VERSION 5.8 ;
BUSBITCHARS "[]" ;
DIVIDERCHAR "/" ;
UNITS
    DATABASE MICRONS 1000 ;
END UNITS

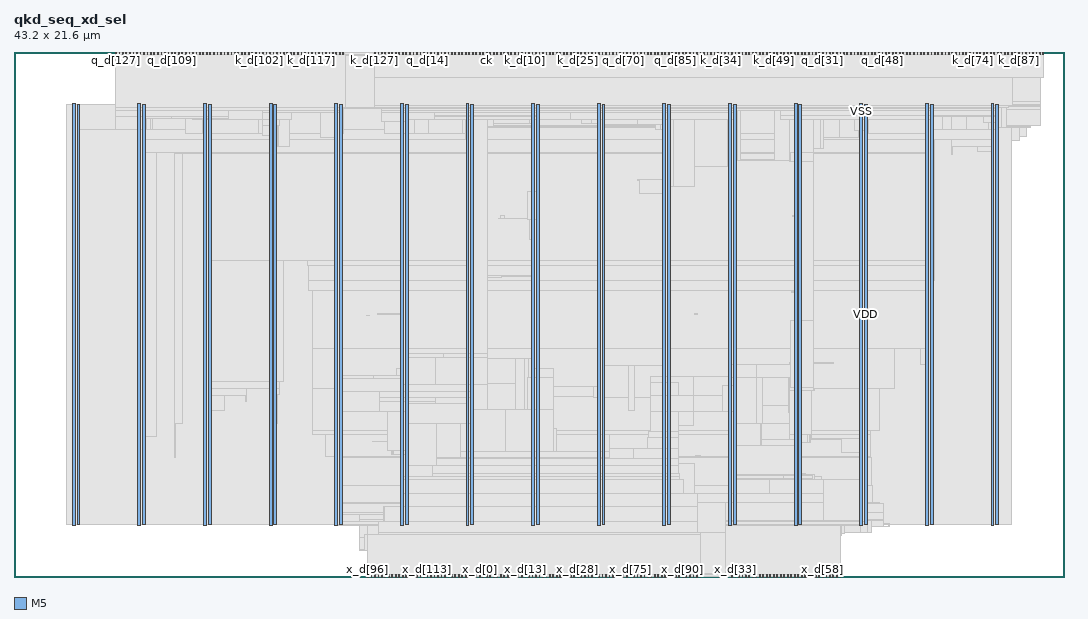
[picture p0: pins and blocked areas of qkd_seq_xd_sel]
MACRO qkd_seq_xd_sel
  FOREIGN qkd_seq_xd_sel 0 0 ;
  CLASS BLOCK ;
  SIZE 43.2 BY 21.6 ;
  PIN ck
    DIRECTION INPUT ;
    USE SIGNAL ;
    PORT
      LAYER M5 ;
        RECT  19.44 21.516 19.464 21.6 ;
    END
  END ck
  PIN k_d[0]
    DIRECTION INPUT ;
    USE SIGNAL ;
    PORT
      LAYER M5 ;
        RECT  19.584 21.516 19.608 21.6 ;
    END
  END k_d[0]
  PIN k_d[100]
    DIRECTION INPUT ;
    USE SIGNAL ;
    PORT
      LAYER M5 ;
        RECT  9.792 21.516 9.816 21.6 ;
    END
  END k_d[100]
  PIN k_d[101]
    DIRECTION INPUT ;
    USE SIGNAL ;
    PORT
      LAYER M5 ;
        RECT  9.936 21.516 9.96 21.6 ;
    END
  END k_d[101]
  PIN k_d[102]
    DIRECTION INPUT ;
    USE SIGNAL ;
    PORT
      LAYER M5 ;
        RECT  10.08 21.516 10.104 21.6 ;
    END
  END k_d[102]
  PIN k_d[103]
    DIRECTION INPUT ;
    USE SIGNAL ;
    PORT
      LAYER M5 ;
        RECT  10.224 21.516 10.248 21.6 ;
    END
  END k_d[103]
  PIN k_d[104]
    DIRECTION INPUT ;
    USE SIGNAL ;
    PORT
      LAYER M5 ;
        RECT  10.368 21.516 10.392 21.6 ;
    END
  END k_d[104]
  PIN k_d[105]
    DIRECTION INPUT ;
    USE SIGNAL ;
    PORT
      LAYER M5 ;
        RECT  10.512 21.516 10.536 21.6 ;
    END
  END k_d[105]
  PIN k_d[106]
    DIRECTION INPUT ;
    USE SIGNAL ;
    PORT
      LAYER M5 ;
        RECT  10.656 21.516 10.68 21.6 ;
    END
  END k_d[106]
  PIN k_d[107]
    DIRECTION INPUT ;
    USE SIGNAL ;
    PORT
      LAYER M5 ;
        RECT  10.8 21.516 10.824 21.6 ;
    END
  END k_d[107]
  PIN k_d[108]
    DIRECTION INPUT ;
    USE SIGNAL ;
    PORT
      LAYER M5 ;
        RECT  10.944 21.516 10.968 21.6 ;
    END
  END k_d[108]
  PIN k_d[109]
    DIRECTION INPUT ;
    USE SIGNAL ;
    PORT
      LAYER M5 ;
        RECT  11.088 21.516 11.112 21.6 ;
    END
  END k_d[109]
  PIN k_d[10]
    DIRECTION INPUT ;
    USE SIGNAL ;
    PORT
      LAYER M5 ;
        RECT  21.024 21.516 21.048 21.6 ;
    END
  END k_d[10]
  PIN k_d[110]
    DIRECTION INPUT ;
    USE SIGNAL ;
    PORT
      LAYER M5 ;
        RECT  11.232 21.516 11.256 21.6 ;
    END
  END k_d[110]
  PIN k_d[111]
    DIRECTION INPUT ;
    USE SIGNAL ;
    PORT
      LAYER M5 ;
        RECT  11.376 21.516 11.4 21.6 ;
    END
  END k_d[111]
  PIN k_d[112]
    DIRECTION INPUT ;
    USE SIGNAL ;
    PORT
      LAYER M5 ;
        RECT  11.52 21.516 11.544 21.6 ;
    END
  END k_d[112]
  PIN k_d[113]
    DIRECTION INPUT ;
    USE SIGNAL ;
    PORT
      LAYER M5 ;
        RECT  11.664 21.516 11.688 21.6 ;
    END
  END k_d[113]
  PIN k_d[114]
    DIRECTION INPUT ;
    USE SIGNAL ;
    PORT
      LAYER M5 ;
        RECT  11.808 21.516 11.832 21.6 ;
    END
  END k_d[114]
  PIN k_d[115]
    DIRECTION INPUT ;
    USE SIGNAL ;
    PORT
      LAYER M5 ;
        RECT  11.952 21.516 11.976 21.6 ;
    END
  END k_d[115]
  PIN k_d[116]
    DIRECTION INPUT ;
    USE SIGNAL ;
    PORT
      LAYER M5 ;
        RECT  12.096 21.516 12.12 21.6 ;
    END
  END k_d[116]
  PIN k_d[117]
    DIRECTION INPUT ;
    USE SIGNAL ;
    PORT
      LAYER M5 ;
        RECT  12.24 21.516 12.264 21.6 ;
    END
  END k_d[117]
  PIN k_d[118]
    DIRECTION INPUT ;
    USE SIGNAL ;
    PORT
      LAYER M5 ;
        RECT  12.384 21.516 12.408 21.6 ;
    END
  END k_d[118]
  PIN k_d[119]
    DIRECTION INPUT ;
    USE SIGNAL ;
    PORT
      LAYER M5 ;
        RECT  12.528 21.516 12.552 21.6 ;
    END
  END k_d[119]
  PIN k_d[11]
    DIRECTION INPUT ;
    USE SIGNAL ;
    PORT
      LAYER M5 ;
        RECT  21.168 21.516 21.192 21.6 ;
    END
  END k_d[11]
  PIN k_d[120]
    DIRECTION INPUT ;
    USE SIGNAL ;
    PORT
      LAYER M5 ;
        RECT  12.672 21.516 12.696 21.6 ;
    END
  END k_d[120]
  PIN k_d[121]
    DIRECTION INPUT ;
    USE SIGNAL ;
    PORT
      LAYER M5 ;
        RECT  12.816 21.516 12.84 21.6 ;
    END
  END k_d[121]
  PIN k_d[122]
    DIRECTION INPUT ;
    USE SIGNAL ;
    PORT
      LAYER M5 ;
        RECT  12.96 21.516 12.984 21.6 ;
    END
  END k_d[122]
  PIN k_d[123]
    DIRECTION INPUT ;
    USE SIGNAL ;
    PORT
      LAYER M5 ;
        RECT  13.104 21.516 13.128 21.6 ;
    END
  END k_d[123]
  PIN k_d[124]
    DIRECTION INPUT ;
    USE SIGNAL ;
    PORT
      LAYER M5 ;
        RECT  13.248 21.516 13.272 21.6 ;
    END
  END k_d[124]
  PIN k_d[125]
    DIRECTION INPUT ;
    USE SIGNAL ;
    PORT
      LAYER M5 ;
        RECT  13.392 21.516 13.416 21.6 ;
    END
  END k_d[125]
  PIN k_d[126]
    DIRECTION INPUT ;
    USE SIGNAL ;
    PORT
      LAYER M5 ;
        RECT  13.536 21.516 13.56 21.6 ;
    END
  END k_d[126]
  PIN k_d[127]
    DIRECTION INPUT ;
    USE SIGNAL ;
    PORT
      LAYER M5 ;
        RECT  14.832 21.516 14.856 21.6 ;
    END
  END k_d[127]
  PIN k_d[12]
    DIRECTION INPUT ;
    USE SIGNAL ;
    PORT
      LAYER M5 ;
        RECT  21.312 21.516 21.336 21.6 ;
    END
  END k_d[12]
  PIN k_d[13]
    DIRECTION INPUT ;
    USE SIGNAL ;
    PORT
      LAYER M5 ;
        RECT  21.456 21.516 21.48 21.6 ;
    END
  END k_d[13]
  PIN k_d[14]
    DIRECTION INPUT ;
    USE SIGNAL ;
    PORT
      LAYER M5 ;
        RECT  21.6 21.516 21.624 21.6 ;
    END
  END k_d[14]
  PIN k_d[15]
    DIRECTION INPUT ;
    USE SIGNAL ;
    PORT
      LAYER M5 ;
        RECT  21.744 21.516 21.768 21.6 ;
    END
  END k_d[15]
  PIN k_d[16]
    DIRECTION INPUT ;
    USE SIGNAL ;
    PORT
      LAYER M5 ;
        RECT  21.888 21.516 21.912 21.6 ;
    END
  END k_d[16]
  PIN k_d[17]
    DIRECTION INPUT ;
    USE SIGNAL ;
    PORT
      LAYER M5 ;
        RECT  22.032 21.516 22.056 21.6 ;
    END
  END k_d[17]
  PIN k_d[18]
    DIRECTION INPUT ;
    USE SIGNAL ;
    PORT
      LAYER M5 ;
        RECT  22.176 21.516 22.2 21.6 ;
    END
  END k_d[18]
  PIN k_d[19]
    DIRECTION INPUT ;
    USE SIGNAL ;
    PORT
      LAYER M5 ;
        RECT  22.32 21.516 22.344 21.6 ;
    END
  END k_d[19]
  PIN k_d[1]
    DIRECTION INPUT ;
    USE SIGNAL ;
    PORT
      LAYER M5 ;
        RECT  19.728 21.516 19.752 21.6 ;
    END
  END k_d[1]
  PIN k_d[20]
    DIRECTION INPUT ;
    USE SIGNAL ;
    PORT
      LAYER M5 ;
        RECT  22.464 21.516 22.488 21.6 ;
    END
  END k_d[20]
  PIN k_d[21]
    DIRECTION INPUT ;
    USE SIGNAL ;
    PORT
      LAYER M5 ;
        RECT  22.608 21.516 22.632 21.6 ;
    END
  END k_d[21]
  PIN k_d[22]
    DIRECTION INPUT ;
    USE SIGNAL ;
    PORT
      LAYER M5 ;
        RECT  22.752 21.516 22.776 21.6 ;
    END
  END k_d[22]
  PIN k_d[23]
    DIRECTION INPUT ;
    USE SIGNAL ;
    PORT
      LAYER M5 ;
        RECT  22.896 21.516 22.92 21.6 ;
    END
  END k_d[23]
  PIN k_d[24]
    DIRECTION INPUT ;
    USE SIGNAL ;
    PORT
      LAYER M5 ;
        RECT  23.04 21.516 23.064 21.6 ;
    END
  END k_d[24]
  PIN k_d[25]
    DIRECTION INPUT ;
    USE SIGNAL ;
    PORT
      LAYER M5 ;
        RECT  23.184 21.516 23.208 21.6 ;
    END
  END k_d[25]
  PIN k_d[26]
    DIRECTION INPUT ;
    USE SIGNAL ;
    PORT
      LAYER M5 ;
        RECT  23.328 21.516 23.352 21.6 ;
    END
  END k_d[26]
  PIN k_d[27]
    DIRECTION INPUT ;
    USE SIGNAL ;
    PORT
      LAYER M5 ;
        RECT  23.472 21.516 23.496 21.6 ;
    END
  END k_d[27]
  PIN k_d[28]
    DIRECTION INPUT ;
    USE SIGNAL ;
    PORT
      LAYER M5 ;
        RECT  23.616 21.516 23.64 21.6 ;
    END
  END k_d[28]
  PIN k_d[29]
    DIRECTION INPUT ;
    USE SIGNAL ;
    PORT
      LAYER M5 ;
        RECT  23.76 21.516 23.784 21.6 ;
    END
  END k_d[29]
  PIN k_d[2]
    DIRECTION INPUT ;
    USE SIGNAL ;
    PORT
      LAYER M5 ;
        RECT  19.872 21.516 19.896 21.6 ;
    END
  END k_d[2]
  PIN k_d[30]
    DIRECTION INPUT ;
    USE SIGNAL ;
    PORT
      LAYER M5 ;
        RECT  23.904 21.516 23.928 21.6 ;
    END
  END k_d[30]
  PIN k_d[31]
    DIRECTION INPUT ;
    USE SIGNAL ;
    PORT
      LAYER M5 ;
        RECT  28.656 21.516 28.68 21.6 ;
    END
  END k_d[31]
  PIN k_d[32]
    DIRECTION INPUT ;
    USE SIGNAL ;
    PORT
      LAYER M5 ;
        RECT  28.8 21.516 28.824 21.6 ;
    END
  END k_d[32]
  PIN k_d[33]
    DIRECTION INPUT ;
    USE SIGNAL ;
    PORT
      LAYER M5 ;
        RECT  28.944 21.516 28.968 21.6 ;
    END
  END k_d[33]
  PIN k_d[34]
    DIRECTION INPUT ;
    USE SIGNAL ;
    PORT
      LAYER M5 ;
        RECT  29.088 21.516 29.112 21.6 ;
    END
  END k_d[34]
  PIN k_d[35]
    DIRECTION INPUT ;
    USE SIGNAL ;
    PORT
      LAYER M5 ;
        RECT  29.232 21.516 29.256 21.6 ;
    END
  END k_d[35]
  PIN k_d[36]
    DIRECTION INPUT ;
    USE SIGNAL ;
    PORT
      LAYER M5 ;
        RECT  29.376 21.516 29.4 21.6 ;
    END
  END k_d[36]
  PIN k_d[37]
    DIRECTION INPUT ;
    USE SIGNAL ;
    PORT
      LAYER M5 ;
        RECT  29.52 21.516 29.544 21.6 ;
    END
  END k_d[37]
  PIN k_d[38]
    DIRECTION INPUT ;
    USE SIGNAL ;
    PORT
      LAYER M5 ;
        RECT  29.664 21.516 29.688 21.6 ;
    END
  END k_d[38]
  PIN k_d[39]
    DIRECTION INPUT ;
    USE SIGNAL ;
    PORT
      LAYER M5 ;
        RECT  29.808 21.516 29.832 21.6 ;
    END
  END k_d[39]
  PIN k_d[3]
    DIRECTION INPUT ;
    USE SIGNAL ;
    PORT
      LAYER M5 ;
        RECT  20.016 21.516 20.04 21.6 ;
    END
  END k_d[3]
  PIN k_d[40]
    DIRECTION INPUT ;
    USE SIGNAL ;
    PORT
      LAYER M5 ;
        RECT  29.952 21.516 29.976 21.6 ;
    END
  END k_d[40]
  PIN k_d[41]
    DIRECTION INPUT ;
    USE SIGNAL ;
    PORT
      LAYER M5 ;
        RECT  30.096 21.516 30.12 21.6 ;
    END
  END k_d[41]
  PIN k_d[42]
    DIRECTION INPUT ;
    USE SIGNAL ;
    PORT
      LAYER M5 ;
        RECT  30.24 21.516 30.264 21.6 ;
    END
  END k_d[42]
  PIN k_d[43]
    DIRECTION INPUT ;
    USE SIGNAL ;
    PORT
      LAYER M5 ;
        RECT  30.384 21.516 30.408 21.6 ;
    END
  END k_d[43]
  PIN k_d[44]
    DIRECTION INPUT ;
    USE SIGNAL ;
    PORT
      LAYER M5 ;
        RECT  30.528 21.516 30.552 21.6 ;
    END
  END k_d[44]
  PIN k_d[45]
    DIRECTION INPUT ;
    USE SIGNAL ;
    PORT
      LAYER M5 ;
        RECT  30.672 21.516 30.696 21.6 ;
    END
  END k_d[45]
  PIN k_d[46]
    DIRECTION INPUT ;
    USE SIGNAL ;
    PORT
      LAYER M5 ;
        RECT  30.816 21.516 30.84 21.6 ;
    END
  END k_d[46]
  PIN k_d[47]
    DIRECTION INPUT ;
    USE SIGNAL ;
    PORT
      LAYER M5 ;
        RECT  30.96 21.516 30.984 21.6 ;
    END
  END k_d[47]
  PIN k_d[48]
    DIRECTION INPUT ;
    USE SIGNAL ;
    PORT
      LAYER M5 ;
        RECT  31.104 21.516 31.128 21.6 ;
    END
  END k_d[48]
  PIN k_d[49]
    DIRECTION INPUT ;
    USE SIGNAL ;
    PORT
      LAYER M5 ;
        RECT  31.248 21.516 31.272 21.6 ;
    END
  END k_d[49]
  PIN k_d[4]
    DIRECTION INPUT ;
    USE SIGNAL ;
    PORT
      LAYER M5 ;
        RECT  20.16 21.516 20.184 21.6 ;
    END
  END k_d[4]
  PIN k_d[50]
    DIRECTION INPUT ;
    USE SIGNAL ;
    PORT
      LAYER M5 ;
        RECT  31.392 21.516 31.416 21.6 ;
    END
  END k_d[50]
  PIN k_d[51]
    DIRECTION INPUT ;
    USE SIGNAL ;
    PORT
      LAYER M5 ;
        RECT  31.536 21.516 31.56 21.6 ;
    END
  END k_d[51]
  PIN k_d[52]
    DIRECTION INPUT ;
    USE SIGNAL ;
    PORT
      LAYER M5 ;
        RECT  31.68 21.516 31.704 21.6 ;
    END
  END k_d[52]
  PIN k_d[53]
    DIRECTION INPUT ;
    USE SIGNAL ;
    PORT
      LAYER M5 ;
        RECT  31.824 21.516 31.848 21.6 ;
    END
  END k_d[53]
  PIN k_d[54]
    DIRECTION INPUT ;
    USE SIGNAL ;
    PORT
      LAYER M5 ;
        RECT  31.968 21.516 31.992 21.6 ;
    END
  END k_d[54]
  PIN k_d[55]
    DIRECTION INPUT ;
    USE SIGNAL ;
    PORT
      LAYER M5 ;
        RECT  32.112 21.516 32.136 21.6 ;
    END
  END k_d[55]
  PIN k_d[56]
    DIRECTION INPUT ;
    USE SIGNAL ;
    PORT
      LAYER M5 ;
        RECT  32.256 21.516 32.28 21.6 ;
    END
  END k_d[56]
  PIN k_d[57]
    DIRECTION INPUT ;
    USE SIGNAL ;
    PORT
      LAYER M5 ;
        RECT  32.4 21.516 32.424 21.6 ;
    END
  END k_d[57]
  PIN k_d[58]
    DIRECTION INPUT ;
    USE SIGNAL ;
    PORT
      LAYER M5 ;
        RECT  32.544 21.516 32.568 21.6 ;
    END
  END k_d[58]
  PIN k_d[59]
    DIRECTION INPUT ;
    USE SIGNAL ;
    PORT
      LAYER M5 ;
        RECT  32.688 21.516 32.712 21.6 ;
    END
  END k_d[59]
  PIN k_d[5]
    DIRECTION INPUT ;
    USE SIGNAL ;
    PORT
      LAYER M5 ;
        RECT  20.304 21.516 20.328 21.6 ;
    END
  END k_d[5]
  PIN k_d[60]
    DIRECTION INPUT ;
    USE SIGNAL ;
    PORT
      LAYER M5 ;
        RECT  32.832 21.516 32.856 21.6 ;
    END
  END k_d[60]
  PIN k_d[61]
    DIRECTION INPUT ;
    USE SIGNAL ;
    PORT
      LAYER M5 ;
        RECT  32.976 21.516 33 21.6 ;
    END
  END k_d[61]
  PIN k_d[62]
    DIRECTION INPUT ;
    USE SIGNAL ;
    PORT
      LAYER M5 ;
        RECT  33.12 21.516 33.144 21.6 ;
    END
  END k_d[62]
  PIN k_d[63]
    DIRECTION INPUT ;
    USE SIGNAL ;
    PORT
      LAYER M5 ;
        RECT  37.872 21.516 37.896 21.6 ;
    END
  END k_d[63]
  PIN k_d[64]
    DIRECTION INPUT ;
    USE SIGNAL ;
    PORT
      LAYER M5 ;
        RECT  38.016 21.516 38.04 21.6 ;
    END
  END k_d[64]
  PIN k_d[65]
    DIRECTION INPUT ;
    USE SIGNAL ;
    PORT
      LAYER M5 ;
        RECT  38.16 21.516 38.184 21.6 ;
    END
  END k_d[65]
  PIN k_d[66]
    DIRECTION INPUT ;
    USE SIGNAL ;
    PORT
      LAYER M5 ;
        RECT  38.304 21.516 38.328 21.6 ;
    END
  END k_d[66]
  PIN k_d[67]
    DIRECTION INPUT ;
    USE SIGNAL ;
    PORT
      LAYER M5 ;
        RECT  38.448 21.516 38.472 21.6 ;
    END
  END k_d[67]
  PIN k_d[68]
    DIRECTION INPUT ;
    USE SIGNAL ;
    PORT
      LAYER M5 ;
        RECT  38.592 21.516 38.616 21.6 ;
    END
  END k_d[68]
  PIN k_d[69]
    DIRECTION INPUT ;
    USE SIGNAL ;
    PORT
      LAYER M5 ;
        RECT  38.736 21.516 38.76 21.6 ;
    END
  END k_d[69]
  PIN k_d[6]
    DIRECTION INPUT ;
    USE SIGNAL ;
    PORT
      LAYER M5 ;
        RECT  20.448 21.516 20.472 21.6 ;
    END
  END k_d[6]
  PIN k_d[70]
    DIRECTION INPUT ;
    USE SIGNAL ;
    PORT
      LAYER M5 ;
        RECT  38.88 21.516 38.904 21.6 ;
    END
  END k_d[70]
  PIN k_d[71]
    DIRECTION INPUT ;
    USE SIGNAL ;
    PORT
      LAYER M5 ;
        RECT  39.024 21.516 39.048 21.6 ;
    END
  END k_d[71]
  PIN k_d[72]
    DIRECTION INPUT ;
    USE SIGNAL ;
    PORT
      LAYER M5 ;
        RECT  39.168 21.516 39.192 21.6 ;
    END
  END k_d[72]
  PIN k_d[73]
    DIRECTION INPUT ;
    USE SIGNAL ;
    PORT
      LAYER M5 ;
        RECT  39.312 21.516 39.336 21.6 ;
    END
  END k_d[73]
  PIN k_d[74]
    DIRECTION INPUT ;
    USE SIGNAL ;
    PORT
      LAYER M5 ;
        RECT  39.456 21.516 39.48 21.6 ;
    END
  END k_d[74]
  PIN k_d[75]
    DIRECTION INPUT ;
    USE SIGNAL ;
    PORT
      LAYER M5 ;
        RECT  39.6 21.516 39.624 21.6 ;
    END
  END k_d[75]
  PIN k_d[76]
    DIRECTION INPUT ;
    USE SIGNAL ;
    PORT
      LAYER M5 ;
        RECT  39.744 21.516 39.768 21.6 ;
    END
  END k_d[76]
  PIN k_d[77]
    DIRECTION INPUT ;
    USE SIGNAL ;
    PORT
      LAYER M5 ;
        RECT  39.888 21.516 39.912 21.6 ;
    END
  END k_d[77]
  PIN k_d[78]
    DIRECTION INPUT ;
    USE SIGNAL ;
    PORT
      LAYER M5 ;
        RECT  40.032 21.516 40.056 21.6 ;
    END
  END k_d[78]
  PIN k_d[79]
    DIRECTION INPUT ;
    USE SIGNAL ;
    PORT
      LAYER M5 ;
        RECT  40.176 21.516 40.2 21.6 ;
    END
  END k_d[79]
  PIN k_d[7]
    DIRECTION INPUT ;
    USE SIGNAL ;
    PORT
      LAYER M5 ;
        RECT  20.592 21.516 20.616 21.6 ;
    END
  END k_d[7]
  PIN k_d[80]
    DIRECTION INPUT ;
    USE SIGNAL ;
    PORT
      LAYER M5 ;
        RECT  40.32 21.516 40.344 21.6 ;
    END
  END k_d[80]
  PIN k_d[81]
    DIRECTION INPUT ;
    USE SIGNAL ;
    PORT
      LAYER M5 ;
        RECT  40.464 21.516 40.488 21.6 ;
    END
  END k_d[81]
  PIN k_d[82]
    DIRECTION INPUT ;
    USE SIGNAL ;
    PORT
      LAYER M5 ;
        RECT  40.608 21.516 40.632 21.6 ;
    END
  END k_d[82]
  PIN k_d[83]
    DIRECTION INPUT ;
    USE SIGNAL ;
    PORT
      LAYER M5 ;
        RECT  40.752 21.516 40.776 21.6 ;
    END
  END k_d[83]
  PIN k_d[84]
    DIRECTION INPUT ;
    USE SIGNAL ;
    PORT
      LAYER M5 ;
        RECT  40.896 21.516 40.92 21.6 ;
    END
  END k_d[84]
  PIN k_d[85]
    DIRECTION INPUT ;
    USE SIGNAL ;
    PORT
      LAYER M5 ;
        RECT  41.04 21.516 41.064 21.6 ;
    END
  END k_d[85]
  PIN k_d[86]
    DIRECTION INPUT ;
    USE SIGNAL ;
    PORT
      LAYER M5 ;
        RECT  41.184 21.516 41.208 21.6 ;
    END
  END k_d[86]
  PIN k_d[87]
    DIRECTION INPUT ;
    USE SIGNAL ;
    PORT
      LAYER M5 ;
        RECT  41.328 21.516 41.352 21.6 ;
    END
  END k_d[87]
  PIN k_d[88]
    DIRECTION INPUT ;
    USE SIGNAL ;
    PORT
      LAYER M5 ;
        RECT  41.472 21.516 41.496 21.6 ;
    END
  END k_d[88]
  PIN k_d[89]
    DIRECTION INPUT ;
    USE SIGNAL ;
    PORT
      LAYER M5 ;
        RECT  41.616 21.516 41.64 21.6 ;
    END
  END k_d[89]
  PIN k_d[8]
    DIRECTION INPUT ;
    USE SIGNAL ;
    PORT
      LAYER M5 ;
        RECT  20.736 21.516 20.76 21.6 ;
    END
  END k_d[8]
  PIN k_d[90]
    DIRECTION INPUT ;
    USE SIGNAL ;
    PORT
      LAYER M5 ;
        RECT  41.76 21.516 41.784 21.6 ;
    END
  END k_d[90]
  PIN k_d[91]
    DIRECTION INPUT ;
    USE SIGNAL ;
    PORT
      LAYER M5 ;
        RECT  41.904 21.516 41.928 21.6 ;
    END
  END k_d[91]
  PIN k_d[92]
    DIRECTION INPUT ;
    USE SIGNAL ;
    PORT
      LAYER M5 ;
        RECT  42.048 21.516 42.072 21.6 ;
    END
  END k_d[92]
  PIN k_d[93]
    DIRECTION INPUT ;
    USE SIGNAL ;
    PORT
      LAYER M5 ;
        RECT  42.192 21.516 42.216 21.6 ;
    END
  END k_d[93]
  PIN k_d[94]
    DIRECTION INPUT ;
    USE SIGNAL ;
    PORT
      LAYER M5 ;
        RECT  42.336 21.516 42.36 21.6 ;
    END
  END k_d[94]
  PIN k_d[95]
    DIRECTION INPUT ;
    USE SIGNAL ;
    PORT
      LAYER M5 ;
        RECT  9.072 21.516 9.096 21.6 ;
    END
  END k_d[95]
  PIN k_d[96]
    DIRECTION INPUT ;
    USE SIGNAL ;
    PORT
      LAYER M5 ;
        RECT  9.216 21.516 9.24 21.6 ;
    END
  END k_d[96]
  PIN k_d[97]
    DIRECTION INPUT ;
    USE SIGNAL ;
    PORT
      LAYER M5 ;
        RECT  9.36 21.516 9.384 21.6 ;
    END
  END k_d[97]
  PIN k_d[98]
    DIRECTION INPUT ;
    USE SIGNAL ;
    PORT
      LAYER M5 ;
        RECT  9.504 21.516 9.528 21.6 ;
    END
  END k_d[98]
  PIN k_d[99]
    DIRECTION INPUT ;
    USE SIGNAL ;
    PORT
      LAYER M5 ;
        RECT  9.648 21.516 9.672 21.6 ;
    END
  END k_d[99]
  PIN k_d[9]
    DIRECTION INPUT ;
    USE SIGNAL ;
    PORT
      LAYER M5 ;
        RECT  20.88 21.516 20.904 21.6 ;
    END
  END k_d[9]
  PIN q_d[0]
    DIRECTION INPUT ;
    USE SIGNAL ;
    PORT
      LAYER M5 ;
        RECT  14.976 21.516 15 21.6 ;
    END
  END q_d[0]
  PIN q_d[100]
    DIRECTION INPUT ;
    USE SIGNAL ;
    PORT
      LAYER M5 ;
        RECT  5.184 21.516 5.208 21.6 ;
    END
  END q_d[100]
  PIN q_d[101]
    DIRECTION INPUT ;
    USE SIGNAL ;
    PORT
      LAYER M5 ;
        RECT  5.328 21.516 5.352 21.6 ;
    END
  END q_d[101]
  PIN q_d[102]
    DIRECTION INPUT ;
    USE SIGNAL ;
    PORT
      LAYER M5 ;
        RECT  5.472 21.516 5.496 21.6 ;
    END
  END q_d[102]
  PIN q_d[103]
    DIRECTION INPUT ;
    USE SIGNAL ;
    PORT
      LAYER M5 ;
        RECT  5.616 21.516 5.64 21.6 ;
    END
  END q_d[103]
  PIN q_d[104]
    DIRECTION INPUT ;
    USE SIGNAL ;
    PORT
      LAYER M5 ;
        RECT  5.76 21.516 5.784 21.6 ;
    END
  END q_d[104]
  PIN q_d[105]
    DIRECTION INPUT ;
    USE SIGNAL ;
    PORT
      LAYER M5 ;
        RECT  5.904 21.516 5.928 21.6 ;
    END
  END q_d[105]
  PIN q_d[106]
    DIRECTION INPUT ;
    USE SIGNAL ;
    PORT
      LAYER M5 ;
        RECT  6.048 21.516 6.072 21.6 ;
    END
  END q_d[106]
  PIN q_d[107]
    DIRECTION INPUT ;
    USE SIGNAL ;
    PORT
      LAYER M5 ;
        RECT  6.192 21.516 6.216 21.6 ;
    END
  END q_d[107]
  PIN q_d[108]
    DIRECTION INPUT ;
    USE SIGNAL ;
    PORT
      LAYER M5 ;
        RECT  6.336 21.516 6.36 21.6 ;
    END
  END q_d[108]
  PIN q_d[109]
    DIRECTION INPUT ;
    USE SIGNAL ;
    PORT
      LAYER M5 ;
        RECT  6.48 21.516 6.504 21.6 ;
    END
  END q_d[109]
  PIN q_d[10]
    DIRECTION INPUT ;
    USE SIGNAL ;
    PORT
      LAYER M5 ;
        RECT  16.416 21.516 16.44 21.6 ;
    END
  END q_d[10]
  PIN q_d[110]
    DIRECTION INPUT ;
    USE SIGNAL ;
    PORT
      LAYER M5 ;
        RECT  6.624 21.516 6.648 21.6 ;
    END
  END q_d[110]
  PIN q_d[111]
    DIRECTION INPUT ;
    USE SIGNAL ;
    PORT
      LAYER M5 ;
        RECT  6.768 21.516 6.792 21.6 ;
    END
  END q_d[111]
  PIN q_d[112]
    DIRECTION INPUT ;
    USE SIGNAL ;
    PORT
      LAYER M5 ;
        RECT  6.912 21.516 6.936 21.6 ;
    END
  END q_d[112]
  PIN q_d[113]
    DIRECTION INPUT ;
    USE SIGNAL ;
    PORT
      LAYER M5 ;
        RECT  7.056 21.516 7.08 21.6 ;
    END
  END q_d[113]
  PIN q_d[114]
    DIRECTION INPUT ;
    USE SIGNAL ;
    PORT
      LAYER M5 ;
        RECT  7.2 21.516 7.224 21.6 ;
    END
  END q_d[114]
  PIN q_d[115]
    DIRECTION INPUT ;
    USE SIGNAL ;
    PORT
      LAYER M5 ;
        RECT  7.344 21.516 7.368 21.6 ;
    END
  END q_d[115]
  PIN q_d[116]
    DIRECTION INPUT ;
    USE SIGNAL ;
    PORT
      LAYER M5 ;
        RECT  7.488 21.516 7.512 21.6 ;
    END
  END q_d[116]
  PIN q_d[117]
    DIRECTION INPUT ;
    USE SIGNAL ;
    PORT
      LAYER M5 ;
        RECT  7.632 21.516 7.656 21.6 ;
    END
  END q_d[117]
  PIN q_d[118]
    DIRECTION INPUT ;
    USE SIGNAL ;
    PORT
      LAYER M5 ;
        RECT  7.776 21.516 7.8 21.6 ;
    END
  END q_d[118]
  PIN q_d[119]
    DIRECTION INPUT ;
    USE SIGNAL ;
    PORT
      LAYER M5 ;
        RECT  7.92 21.516 7.944 21.6 ;
    END
  END q_d[119]
  PIN q_d[11]
    DIRECTION INPUT ;
    USE SIGNAL ;
    PORT
      LAYER M5 ;
        RECT  16.56 21.516 16.584 21.6 ;
    END
  END q_d[11]
  PIN q_d[120]
    DIRECTION INPUT ;
    USE SIGNAL ;
    PORT
      LAYER M5 ;
        RECT  8.064 21.516 8.088 21.6 ;
    END
  END q_d[120]
  PIN q_d[121]
    DIRECTION INPUT ;
    USE SIGNAL ;
    PORT
      LAYER M5 ;
        RECT  8.208 21.516 8.232 21.6 ;
    END
  END q_d[121]
  PIN q_d[122]
    DIRECTION INPUT ;
    USE SIGNAL ;
    PORT
      LAYER M5 ;
        RECT  8.352 21.516 8.376 21.6 ;
    END
  END q_d[122]
  PIN q_d[123]
    DIRECTION INPUT ;
    USE SIGNAL ;
    PORT
      LAYER M5 ;
        RECT  8.496 21.516 8.52 21.6 ;
    END
  END q_d[123]
  PIN q_d[124]
    DIRECTION INPUT ;
    USE SIGNAL ;
    PORT
      LAYER M5 ;
        RECT  8.64 21.516 8.664 21.6 ;
    END
  END q_d[124]
  PIN q_d[125]
    DIRECTION INPUT ;
    USE SIGNAL ;
    PORT
      LAYER M5 ;
        RECT  8.784 21.516 8.808 21.6 ;
    END
  END q_d[125]
  PIN q_d[126]
    DIRECTION INPUT ;
    USE SIGNAL ;
    PORT
      LAYER M5 ;
        RECT  8.928 21.516 8.952 21.6 ;
    END
  END q_d[126]
  PIN q_d[127]
    DIRECTION INPUT ;
    USE SIGNAL ;
    PORT
      LAYER M5 ;
        RECT  4.176 21.516 4.2 21.6 ;
    END
  END q_d[127]
  PIN q_d[12]
    DIRECTION INPUT ;
    USE SIGNAL ;
    PORT
      LAYER M5 ;
        RECT  16.704 21.516 16.728 21.6 ;
    END
  END q_d[12]
  PIN q_d[13]
    DIRECTION INPUT ;
    USE SIGNAL ;
    PORT
      LAYER M5 ;
        RECT  16.848 21.516 16.872 21.6 ;
    END
  END q_d[13]
  PIN q_d[14]
    DIRECTION INPUT ;
    USE SIGNAL ;
    PORT
      LAYER M5 ;
        RECT  16.992 21.516 17.016 21.6 ;
    END
  END q_d[14]
  PIN q_d[15]
    DIRECTION INPUT ;
    USE SIGNAL ;
    PORT
      LAYER M5 ;
        RECT  17.136 21.516 17.16 21.6 ;
    END
  END q_d[15]
  PIN q_d[16]
    DIRECTION INPUT ;
    USE SIGNAL ;
    PORT
      LAYER M5 ;
        RECT  17.28 21.516 17.304 21.6 ;
    END
  END q_d[16]
  PIN q_d[17]
    DIRECTION INPUT ;
    USE SIGNAL ;
    PORT
      LAYER M5 ;
        RECT  17.424 21.516 17.448 21.6 ;
    END
  END q_d[17]
  PIN q_d[18]
    DIRECTION INPUT ;
    USE SIGNAL ;
    PORT
      LAYER M5 ;
        RECT  17.568 21.516 17.592 21.6 ;
    END
  END q_d[18]
  PIN q_d[19]
    DIRECTION INPUT ;
    USE SIGNAL ;
    PORT
      LAYER M5 ;
        RECT  17.712 21.516 17.736 21.6 ;
    END
  END q_d[19]
  PIN q_d[1]
    DIRECTION INPUT ;
    USE SIGNAL ;
    PORT
      LAYER M5 ;
        RECT  15.12 21.516 15.144 21.6 ;
    END
  END q_d[1]
  PIN q_d[20]
    DIRECTION INPUT ;
    USE SIGNAL ;
    PORT
      LAYER M5 ;
        RECT  17.856 21.516 17.88 21.6 ;
    END
  END q_d[20]
  PIN q_d[21]
    DIRECTION INPUT ;
    USE SIGNAL ;
    PORT
      LAYER M5 ;
        RECT  18 21.516 18.024 21.6 ;
    END
  END q_d[21]
  PIN q_d[22]
    DIRECTION INPUT ;
    USE SIGNAL ;
    PORT
      LAYER M5 ;
        RECT  18.144 21.516 18.168 21.6 ;
    END
  END q_d[22]
  PIN q_d[23]
    DIRECTION INPUT ;
    USE SIGNAL ;
    PORT
      LAYER M5 ;
        RECT  18.288 21.516 18.312 21.6 ;
    END
  END q_d[23]
  PIN q_d[24]
    DIRECTION INPUT ;
    USE SIGNAL ;
    PORT
      LAYER M5 ;
        RECT  18.432 21.516 18.456 21.6 ;
    END
  END q_d[24]
  PIN q_d[25]
    DIRECTION INPUT ;
    USE SIGNAL ;
    PORT
      LAYER M5 ;
        RECT  18.576 21.516 18.6 21.6 ;
    END
  END q_d[25]
  PIN q_d[26]
    DIRECTION INPUT ;
    USE SIGNAL ;
    PORT
      LAYER M5 ;
        RECT  18.72 21.516 18.744 21.6 ;
    END
  END q_d[26]
  PIN q_d[27]
    DIRECTION INPUT ;
    USE SIGNAL ;
    PORT
      LAYER M5 ;
        RECT  18.864 21.516 18.888 21.6 ;
    END
  END q_d[27]
  PIN q_d[28]
    DIRECTION INPUT ;
    USE SIGNAL ;
    PORT
      LAYER M5 ;
        RECT  19.008 21.516 19.032 21.6 ;
    END
  END q_d[28]
  PIN q_d[29]
    DIRECTION INPUT ;
    USE SIGNAL ;
    PORT
      LAYER M5 ;
        RECT  19.152 21.516 19.176 21.6 ;
    END
  END q_d[29]
  PIN q_d[2]
    DIRECTION INPUT ;
    USE SIGNAL ;
    PORT
      LAYER M5 ;
        RECT  15.264 21.516 15.288 21.6 ;
    END
  END q_d[2]
  PIN q_d[30]
    DIRECTION INPUT ;
    USE SIGNAL ;
    PORT
      LAYER M5 ;
        RECT  19.296 21.516 19.32 21.6 ;
    END
  END q_d[30]
  PIN q_d[31]
    DIRECTION INPUT ;
    USE SIGNAL ;
    PORT
      LAYER M5 ;
        RECT  33.264 21.516 33.288 21.6 ;
    END
  END q_d[31]
  PIN q_d[32]
    DIRECTION INPUT ;
    USE SIGNAL ;
    PORT
      LAYER M5 ;
        RECT  33.408 21.516 33.432 21.6 ;
    END
  END q_d[32]
  PIN q_d[33]
    DIRECTION INPUT ;
    USE SIGNAL ;
    PORT
      LAYER M5 ;
        RECT  33.552 21.516 33.576 21.6 ;
    END
  END q_d[33]
  PIN q_d[34]
    DIRECTION INPUT ;
    USE SIGNAL ;
    PORT
      LAYER M5 ;
        RECT  33.696 21.516 33.72 21.6 ;
    END
  END q_d[34]
  PIN q_d[35]
    DIRECTION INPUT ;
    USE SIGNAL ;
    PORT
      LAYER M5 ;
        RECT  33.84 21.516 33.864 21.6 ;
    END
  END q_d[35]
  PIN q_d[36]
    DIRECTION INPUT ;
    USE SIGNAL ;
    PORT
      LAYER M5 ;
        RECT  33.984 21.516 34.008 21.6 ;
    END
  END q_d[36]
  PIN q_d[37]
    DIRECTION INPUT ;
    USE SIGNAL ;
    PORT
      LAYER M5 ;
        RECT  34.128 21.516 34.152 21.6 ;
    END
  END q_d[37]
  PIN q_d[38]
    DIRECTION INPUT ;
    USE SIGNAL ;
    PORT
      LAYER M5 ;
        RECT  34.272 21.516 34.296 21.6 ;
    END
  END q_d[38]
  PIN q_d[39]
    DIRECTION INPUT ;
    USE SIGNAL ;
    PORT
      LAYER M5 ;
        RECT  34.416 21.516 34.44 21.6 ;
    END
  END q_d[39]
  PIN q_d[3]
    DIRECTION INPUT ;
    USE SIGNAL ;
    PORT
      LAYER M5 ;
        RECT  15.408 21.516 15.432 21.6 ;
    END
  END q_d[3]
  PIN q_d[40]
    DIRECTION INPUT ;
    USE SIGNAL ;
    PORT
      LAYER M5 ;
        RECT  34.56 21.516 34.584 21.6 ;
    END
  END q_d[40]
  PIN q_d[41]
    DIRECTION INPUT ;
    USE SIGNAL ;
    PORT
      LAYER M5 ;
        RECT  34.704 21.516 34.728 21.6 ;
    END
  END q_d[41]
  PIN q_d[42]
    DIRECTION INPUT ;
    USE SIGNAL ;
    PORT
      LAYER M5 ;
        RECT  34.848 21.516 34.872 21.6 ;
    END
  END q_d[42]
  PIN q_d[43]
    DIRECTION INPUT ;
    USE SIGNAL ;
    PORT
      LAYER M5 ;
        RECT  34.992 21.516 35.016 21.6 ;
    END
  END q_d[43]
  PIN q_d[44]
    DIRECTION INPUT ;
    USE SIGNAL ;
    PORT
      LAYER M5 ;
        RECT  35.136 21.516 35.16 21.6 ;
    END
  END q_d[44]
  PIN q_d[45]
    DIRECTION INPUT ;
    USE SIGNAL ;
    PORT
      LAYER M5 ;
        RECT  35.28 21.516 35.304 21.6 ;
    END
  END q_d[45]
  PIN q_d[46]
    DIRECTION INPUT ;
    USE SIGNAL ;
    PORT
      LAYER M5 ;
        RECT  35.424 21.516 35.448 21.6 ;
    END
  END q_d[46]
  PIN q_d[47]
    DIRECTION INPUT ;
    USE SIGNAL ;
    PORT
      LAYER M5 ;
        RECT  35.568 21.516 35.592 21.6 ;
    END
  END q_d[47]
  PIN q_d[48]
    DIRECTION INPUT ;
    USE SIGNAL ;
    PORT
      LAYER M5 ;
        RECT  35.712 21.516 35.736 21.6 ;
    END
  END q_d[48]
  PIN q_d[49]
    DIRECTION INPUT ;
    USE SIGNAL ;
    PORT
      LAYER M5 ;
        RECT  35.856 21.516 35.88 21.6 ;
    END
  END q_d[49]
  PIN q_d[4]
    DIRECTION INPUT ;
    USE SIGNAL ;
    PORT
      LAYER M5 ;
        RECT  15.552 21.516 15.576 21.6 ;
    END
  END q_d[4]
  PIN q_d[50]
    DIRECTION INPUT ;
    USE SIGNAL ;
    PORT
      LAYER M5 ;
        RECT  36 21.516 36.024 21.6 ;
    END
  END q_d[50]
  PIN q_d[51]
    DIRECTION INPUT ;
    USE SIGNAL ;
    PORT
      LAYER M5 ;
        RECT  36.144 21.516 36.168 21.6 ;
    END
  END q_d[51]
  PIN q_d[52]
    DIRECTION INPUT ;
    USE SIGNAL ;
    PORT
      LAYER M5 ;
        RECT  36.288 21.516 36.312 21.6 ;
    END
  END q_d[52]
  PIN q_d[53]
    DIRECTION INPUT ;
    USE SIGNAL ;
    PORT
      LAYER M5 ;
        RECT  36.432 21.516 36.456 21.6 ;
    END
  END q_d[53]
  PIN q_d[54]
    DIRECTION INPUT ;
    USE SIGNAL ;
    PORT
      LAYER M5 ;
        RECT  36.576 21.516 36.6 21.6 ;
    END
  END q_d[54]
  PIN q_d[55]
    DIRECTION INPUT ;
    USE SIGNAL ;
    PORT
      LAYER M5 ;
        RECT  36.72 21.516 36.744 21.6 ;
    END
  END q_d[55]
  PIN q_d[56]
    DIRECTION INPUT ;
    USE SIGNAL ;
    PORT
      LAYER M5 ;
        RECT  36.864 21.516 36.888 21.6 ;
    END
  END q_d[56]
  PIN q_d[57]
    DIRECTION INPUT ;
    USE SIGNAL ;
    PORT
      LAYER M5 ;
        RECT  37.008 21.516 37.032 21.6 ;
    END
  END q_d[57]
  PIN q_d[58]
    DIRECTION INPUT ;
    USE SIGNAL ;
    PORT
      LAYER M5 ;
        RECT  37.152 21.516 37.176 21.6 ;
    END
  END q_d[58]
  PIN q_d[59]
    DIRECTION INPUT ;
    USE SIGNAL ;
    PORT
      LAYER M5 ;
        RECT  37.296 21.516 37.32 21.6 ;
    END
  END q_d[59]
  PIN q_d[5]
    DIRECTION INPUT ;
    USE SIGNAL ;
    PORT
      LAYER M5 ;
        RECT  15.696 21.516 15.72 21.6 ;
    END
  END q_d[5]
  PIN q_d[60]
    DIRECTION INPUT ;
    USE SIGNAL ;
    PORT
      LAYER M5 ;
        RECT  37.44 21.516 37.464 21.6 ;
    END
  END q_d[60]
  PIN q_d[61]
    DIRECTION INPUT ;
    USE SIGNAL ;
    PORT
      LAYER M5 ;
        RECT  37.584 21.516 37.608 21.6 ;
    END
  END q_d[61]
  PIN q_d[62]
    DIRECTION INPUT ;
    USE SIGNAL ;
    PORT
      LAYER M5 ;
        RECT  37.728 21.516 37.752 21.6 ;
    END
  END q_d[62]
  PIN q_d[63]
    DIRECTION INPUT ;
    USE SIGNAL ;
    PORT
      LAYER M5 ;
        RECT  24.048 21.516 24.072 21.6 ;
    END
  END q_d[63]
  PIN q_d[64]
    DIRECTION INPUT ;
    USE SIGNAL ;
    PORT
      LAYER M5 ;
        RECT  24.192 21.516 24.216 21.6 ;
    END
  END q_d[64]
  PIN q_d[65]
    DIRECTION INPUT ;
    USE SIGNAL ;
    PORT
      LAYER M5 ;
        RECT  24.336 21.516 24.36 21.6 ;
    END
  END q_d[65]
  PIN q_d[66]
    DIRECTION INPUT ;
    USE SIGNAL ;
    PORT
      LAYER M5 ;
        RECT  24.48 21.516 24.504 21.6 ;
    END
  END q_d[66]
  PIN q_d[67]
    DIRECTION INPUT ;
    USE SIGNAL ;
    PORT
      LAYER M5 ;
        RECT  24.624 21.516 24.648 21.6 ;
    END
  END q_d[67]
  PIN q_d[68]
    DIRECTION INPUT ;
    USE SIGNAL ;
    PORT
      LAYER M5 ;
        RECT  24.768 21.516 24.792 21.6 ;
    END
  END q_d[68]
  PIN q_d[69]
    DIRECTION INPUT ;
    USE SIGNAL ;
    PORT
      LAYER M5 ;
        RECT  24.912 21.516 24.936 21.6 ;
    END
  END q_d[69]
  PIN q_d[6]
    DIRECTION INPUT ;
    USE SIGNAL ;
    PORT
      LAYER M5 ;
        RECT  15.84 21.516 15.864 21.6 ;
    END
  END q_d[6]
  PIN q_d[70]
    DIRECTION INPUT ;
    USE SIGNAL ;
    PORT
      LAYER M5 ;
        RECT  25.056 21.516 25.08 21.6 ;
    END
  END q_d[70]
  PIN q_d[71]
    DIRECTION INPUT ;
    USE SIGNAL ;
    PORT
      LAYER M5 ;
        RECT  25.2 21.516 25.224 21.6 ;
    END
  END q_d[71]
  PIN q_d[72]
    DIRECTION INPUT ;
    USE SIGNAL ;
    PORT
      LAYER M5 ;
        RECT  25.344 21.516 25.368 21.6 ;
    END
  END q_d[72]
  PIN q_d[73]
    DIRECTION INPUT ;
    USE SIGNAL ;
    PORT
      LAYER M5 ;
        RECT  25.488 21.516 25.512 21.6 ;
    END
  END q_d[73]
  PIN q_d[74]
    DIRECTION INPUT ;
    USE SIGNAL ;
    PORT
      LAYER M5 ;
        RECT  25.632 21.516 25.656 21.6 ;
    END
  END q_d[74]
  PIN q_d[75]
    DIRECTION INPUT ;
    USE SIGNAL ;
    PORT
      LAYER M5 ;
        RECT  25.776 21.516 25.8 21.6 ;
    END
  END q_d[75]
  PIN q_d[76]
    DIRECTION INPUT ;
    USE SIGNAL ;
    PORT
      LAYER M5 ;
        RECT  25.92 21.516 25.944 21.6 ;
    END
  END q_d[76]
  PIN q_d[77]
    DIRECTION INPUT ;
    USE SIGNAL ;
    PORT
      LAYER M5 ;
        RECT  26.064 21.516 26.088 21.6 ;
    END
  END q_d[77]
  PIN q_d[78]
    DIRECTION INPUT ;
    USE SIGNAL ;
    PORT
      LAYER M5 ;
        RECT  26.208 21.516 26.232 21.6 ;
    END
  END q_d[78]
  PIN q_d[79]
    DIRECTION INPUT ;
    USE SIGNAL ;
    PORT
      LAYER M5 ;
        RECT  26.352 21.516 26.376 21.6 ;
    END
  END q_d[79]
  PIN q_d[7]
    DIRECTION INPUT ;
    USE SIGNAL ;
    PORT
      LAYER M5 ;
        RECT  15.984 21.516 16.008 21.6 ;
    END
  END q_d[7]
  PIN q_d[80]
    DIRECTION INPUT ;
    USE SIGNAL ;
    PORT
      LAYER M5 ;
        RECT  26.496 21.516 26.52 21.6 ;
    END
  END q_d[80]
  PIN q_d[81]
    DIRECTION INPUT ;
    USE SIGNAL ;
    PORT
      LAYER M5 ;
        RECT  26.64 21.516 26.664 21.6 ;
    END
  END q_d[81]
  PIN q_d[82]
    DIRECTION INPUT ;
    USE SIGNAL ;
    PORT
      LAYER M5 ;
        RECT  26.784 21.516 26.808 21.6 ;
    END
  END q_d[82]
  PIN q_d[83]
    DIRECTION INPUT ;
    USE SIGNAL ;
    PORT
      LAYER M5 ;
        RECT  26.928 21.516 26.952 21.6 ;
    END
  END q_d[83]
  PIN q_d[84]
    DIRECTION INPUT ;
    USE SIGNAL ;
    PORT
      LAYER M5 ;
        RECT  27.072 21.516 27.096 21.6 ;
    END
  END q_d[84]
  PIN q_d[85]
    DIRECTION INPUT ;
    USE SIGNAL ;
    PORT
      LAYER M5 ;
        RECT  27.216 21.516 27.24 21.6 ;
    END
  END q_d[85]
  PIN q_d[86]
    DIRECTION INPUT ;
    USE SIGNAL ;
    PORT
      LAYER M5 ;
        RECT  27.36 21.516 27.384 21.6 ;
    END
  END q_d[86]
  PIN q_d[87]
    DIRECTION INPUT ;
    USE SIGNAL ;
    PORT
      LAYER M5 ;
        RECT  27.504 21.516 27.528 21.6 ;
    END
  END q_d[87]
  PIN q_d[88]
    DIRECTION INPUT ;
    USE SIGNAL ;
    PORT
      LAYER M5 ;
        RECT  27.648 21.516 27.672 21.6 ;
    END
  END q_d[88]
  PIN q_d[89]
    DIRECTION INPUT ;
    USE SIGNAL ;
    PORT
      LAYER M5 ;
        RECT  27.792 21.516 27.816 21.6 ;
    END
  END q_d[89]
  PIN q_d[8]
    DIRECTION INPUT ;
    USE SIGNAL ;
    PORT
      LAYER M5 ;
        RECT  16.128 21.516 16.152 21.6 ;
    END
  END q_d[8]
  PIN q_d[90]
    DIRECTION INPUT ;
    USE SIGNAL ;
    PORT
      LAYER M5 ;
        RECT  27.936 21.516 27.96 21.6 ;
    END
  END q_d[90]
  PIN q_d[91]
    DIRECTION INPUT ;
    USE SIGNAL ;
    PORT
      LAYER M5 ;
        RECT  28.08 21.516 28.104 21.6 ;
    END
  END q_d[91]
  PIN q_d[92]
    DIRECTION INPUT ;
    USE SIGNAL ;
    PORT
      LAYER M5 ;
        RECT  28.224 21.516 28.248 21.6 ;
    END
  END q_d[92]
  PIN q_d[93]
    DIRECTION INPUT ;
    USE SIGNAL ;
    PORT
      LAYER M5 ;
        RECT  28.368 21.516 28.392 21.6 ;
    END
  END q_d[93]
  PIN q_d[94]
    DIRECTION INPUT ;
    USE SIGNAL ;
    PORT
      LAYER M5 ;
        RECT  28.512 21.516 28.536 21.6 ;
    END
  END q_d[94]
  PIN q_d[95]
    DIRECTION INPUT ;
    USE SIGNAL ;
    PORT
      LAYER M5 ;
        RECT  4.464 21.516 4.488 21.6 ;
    END
  END q_d[95]
  PIN q_d[96]
    DIRECTION INPUT ;
    USE SIGNAL ;
    PORT
      LAYER M5 ;
        RECT  4.608 21.516 4.632 21.6 ;
    END
  END q_d[96]
  PIN q_d[97]
    DIRECTION INPUT ;
    USE SIGNAL ;
    PORT
      LAYER M5 ;
        RECT  4.752 21.516 4.776 21.6 ;
    END
  END q_d[97]
  PIN q_d[98]
    DIRECTION INPUT ;
    USE SIGNAL ;
    PORT
      LAYER M5 ;
        RECT  4.896 21.516 4.92 21.6 ;
    END
  END q_d[98]
  PIN q_d[99]
    DIRECTION INPUT ;
    USE SIGNAL ;
    PORT
      LAYER M5 ;
        RECT  5.04 21.516 5.064 21.6 ;
    END
  END q_d[99]
  PIN q_d[9]
    DIRECTION INPUT ;
    USE SIGNAL ;
    PORT
      LAYER M5 ;
        RECT  16.272 21.516 16.296 21.6 ;
    END
  END q_d[9]
  PIN q_v
    DIRECTION INPUT ;
    USE SIGNAL ;
    PORT
      LAYER M5 ;
        RECT  4.32 21.516 4.344 21.6 ;
    END
  END q_v
  PIN x_d[0]
    DIRECTION OUTPUT ;
    USE SIGNAL ;
    PORT
      LAYER M5 ;
        RECT  19.152 0 19.176 0.084 ;
    END
  END x_d[0]
  PIN x_d[100]
    DIRECTION OUTPUT ;
    USE SIGNAL ;
    PORT
      LAYER M5 ;
        RECT  15.12 0 15.144 0.084 ;
    END
  END x_d[100]
  PIN x_d[101]
    DIRECTION OUTPUT ;
    USE SIGNAL ;
    PORT
      LAYER M5 ;
        RECT  15.264 0 15.288 0.084 ;
    END
  END x_d[101]
  PIN x_d[102]
    DIRECTION OUTPUT ;
    USE SIGNAL ;
    PORT
      LAYER M5 ;
        RECT  15.408 0 15.432 0.084 ;
    END
  END x_d[102]
  PIN x_d[103]
    DIRECTION OUTPUT ;
    USE SIGNAL ;
    PORT
      LAYER M5 ;
        RECT  15.552 0 15.576 0.084 ;
    END
  END x_d[103]
  PIN x_d[104]
    DIRECTION OUTPUT ;
    USE SIGNAL ;
    PORT
      LAYER M5 ;
        RECT  15.696 0 15.72 0.084 ;
    END
  END x_d[104]
  PIN x_d[105]
    DIRECTION OUTPUT ;
    USE SIGNAL ;
    PORT
      LAYER M5 ;
        RECT  15.84 0 15.864 0.084 ;
    END
  END x_d[105]
  PIN x_d[106]
    DIRECTION OUTPUT ;
    USE SIGNAL ;
    PORT
      LAYER M5 ;
        RECT  15.984 0 16.008 0.084 ;
    END
  END x_d[106]
  PIN x_d[107]
    DIRECTION OUTPUT ;
    USE SIGNAL ;
    PORT
      LAYER M5 ;
        RECT  16.128 0 16.152 0.084 ;
    END
  END x_d[107]
  PIN x_d[108]
    DIRECTION OUTPUT ;
    USE SIGNAL ;
    PORT
      LAYER M5 ;
        RECT  16.272 0 16.296 0.084 ;
    END
  END x_d[108]
  PIN x_d[109]
    DIRECTION OUTPUT ;
    USE SIGNAL ;
    PORT
      LAYER M5 ;
        RECT  16.416 0 16.44 0.084 ;
    END
  END x_d[109]
  PIN x_d[10]
    DIRECTION OUTPUT ;
    USE SIGNAL ;
    PORT
      LAYER M5 ;
        RECT  20.592 0 20.616 0.084 ;
    END
  END x_d[10]
  PIN x_d[110]
    DIRECTION OUTPUT ;
    USE SIGNAL ;
    PORT
      LAYER M5 ;
        RECT  16.56 0 16.584 0.084 ;
    END
  END x_d[110]
  PIN x_d[111]
    DIRECTION OUTPUT ;
    USE SIGNAL ;
    PORT
      LAYER M5 ;
        RECT  16.704 0 16.728 0.084 ;
    END
  END x_d[111]
  PIN x_d[112]
    DIRECTION OUTPUT ;
    USE SIGNAL ;
    PORT
      LAYER M5 ;
        RECT  16.848 0 16.872 0.084 ;
    END
  END x_d[112]
  PIN x_d[113]
    DIRECTION OUTPUT ;
    USE SIGNAL ;
    PORT
      LAYER M5 ;
        RECT  16.992 0 17.016 0.084 ;
    END
  END x_d[113]
  PIN x_d[114]
    DIRECTION OUTPUT ;
    USE SIGNAL ;
    PORT
      LAYER M5 ;
        RECT  17.136 0 17.16 0.084 ;
    END
  END x_d[114]
  PIN x_d[115]
    DIRECTION OUTPUT ;
    USE SIGNAL ;
    PORT
      LAYER M5 ;
        RECT  17.28 0 17.304 0.084 ;
    END
  END x_d[115]
  PIN x_d[116]
    DIRECTION OUTPUT ;
    USE SIGNAL ;
    PORT
      LAYER M5 ;
        RECT  17.424 0 17.448 0.084 ;
    END
  END x_d[116]
  PIN x_d[117]
    DIRECTION OUTPUT ;
    USE SIGNAL ;
    PORT
      LAYER M5 ;
        RECT  17.568 0 17.592 0.084 ;
    END
  END x_d[117]
  PIN x_d[118]
    DIRECTION OUTPUT ;
    USE SIGNAL ;
    PORT
      LAYER M5 ;
        RECT  17.712 0 17.736 0.084 ;
    END
  END x_d[118]
  PIN x_d[119]
    DIRECTION OUTPUT ;
    USE SIGNAL ;
    PORT
      LAYER M5 ;
        RECT  17.856 0 17.88 0.084 ;
    END
  END x_d[119]
  PIN x_d[11]
    DIRECTION OUTPUT ;
    USE SIGNAL ;
    PORT
      LAYER M5 ;
        RECT  20.736 0 20.76 0.084 ;
    END
  END x_d[11]
  PIN x_d[120]
    DIRECTION OUTPUT ;
    USE SIGNAL ;
    PORT
      LAYER M5 ;
        RECT  18 0 18.024 0.084 ;
    END
  END x_d[120]
  PIN x_d[121]
    DIRECTION OUTPUT ;
    USE SIGNAL ;
    PORT
      LAYER M5 ;
        RECT  18.144 0 18.168 0.084 ;
    END
  END x_d[121]
  PIN x_d[122]
    DIRECTION OUTPUT ;
    USE SIGNAL ;
    PORT
      LAYER M5 ;
        RECT  18.288 0 18.312 0.084 ;
    END
  END x_d[122]
  PIN x_d[123]
    DIRECTION OUTPUT ;
    USE SIGNAL ;
    PORT
      LAYER M5 ;
        RECT  18.432 0 18.456 0.084 ;
    END
  END x_d[123]
  PIN x_d[124]
    DIRECTION OUTPUT ;
    USE SIGNAL ;
    PORT
      LAYER M5 ;
        RECT  18.576 0 18.6 0.084 ;
    END
  END x_d[124]
  PIN x_d[125]
    DIRECTION OUTPUT ;
    USE SIGNAL ;
    PORT
      LAYER M5 ;
        RECT  18.72 0 18.744 0.084 ;
    END
  END x_d[125]
  PIN x_d[126]
    DIRECTION OUTPUT ;
    USE SIGNAL ;
    PORT
      LAYER M5 ;
        RECT  18.864 0 18.888 0.084 ;
    END
  END x_d[126]
  PIN x_d[127]
    DIRECTION OUTPUT ;
    USE SIGNAL ;
    PORT
      LAYER M5 ;
        RECT  19.008 0 19.032 0.084 ;
    END
  END x_d[127]
  PIN x_d[12]
    DIRECTION OUTPUT ;
    USE SIGNAL ;
    PORT
      LAYER M5 ;
        RECT  20.88 0 20.904 0.084 ;
    END
  END x_d[12]
  PIN x_d[13]
    DIRECTION OUTPUT ;
    USE SIGNAL ;
    PORT
      LAYER M5 ;
        RECT  21.024 0 21.048 0.084 ;
    END
  END x_d[13]
  PIN x_d[14]
    DIRECTION OUTPUT ;
    USE SIGNAL ;
    PORT
      LAYER M5 ;
        RECT  21.168 0 21.192 0.084 ;
    END
  END x_d[14]
  PIN x_d[15]
    DIRECTION OUTPUT ;
    USE SIGNAL ;
    PORT
      LAYER M5 ;
        RECT  21.312 0 21.336 0.084 ;
    END
  END x_d[15]
  PIN x_d[16]
    DIRECTION OUTPUT ;
    USE SIGNAL ;
    PORT
      LAYER M5 ;
        RECT  21.456 0 21.48 0.084 ;
    END
  END x_d[16]
  PIN x_d[17]
    DIRECTION OUTPUT ;
    USE SIGNAL ;
    PORT
      LAYER M5 ;
        RECT  21.6 0 21.624 0.084 ;
    END
  END x_d[17]
  PIN x_d[18]
    DIRECTION OUTPUT ;
    USE SIGNAL ;
    PORT
      LAYER M5 ;
        RECT  21.744 0 21.768 0.084 ;
    END
  END x_d[18]
  PIN x_d[19]
    DIRECTION OUTPUT ;
    USE SIGNAL ;
    PORT
      LAYER M5 ;
        RECT  21.888 0 21.912 0.084 ;
    END
  END x_d[19]
  PIN x_d[1]
    DIRECTION OUTPUT ;
    USE SIGNAL ;
    PORT
      LAYER M5 ;
        RECT  19.296 0 19.32 0.084 ;
    END
  END x_d[1]
  PIN x_d[20]
    DIRECTION OUTPUT ;
    USE SIGNAL ;
    PORT
      LAYER M5 ;
        RECT  22.032 0 22.056 0.084 ;
    END
  END x_d[20]
  PIN x_d[21]
    DIRECTION OUTPUT ;
    USE SIGNAL ;
    PORT
      LAYER M5 ;
        RECT  22.176 0 22.2 0.084 ;
    END
  END x_d[21]
  PIN x_d[22]
    DIRECTION OUTPUT ;
    USE SIGNAL ;
    PORT
      LAYER M5 ;
        RECT  22.32 0 22.344 0.084 ;
    END
  END x_d[22]
  PIN x_d[23]
    DIRECTION OUTPUT ;
    USE SIGNAL ;
    PORT
      LAYER M5 ;
        RECT  22.464 0 22.488 0.084 ;
    END
  END x_d[23]
  PIN x_d[24]
    DIRECTION OUTPUT ;
    USE SIGNAL ;
    PORT
      LAYER M5 ;
        RECT  22.608 0 22.632 0.084 ;
    END
  END x_d[24]
  PIN x_d[25]
    DIRECTION OUTPUT ;
    USE SIGNAL ;
    PORT
      LAYER M5 ;
        RECT  22.752 0 22.776 0.084 ;
    END
  END x_d[25]
  PIN x_d[26]
    DIRECTION OUTPUT ;
    USE SIGNAL ;
    PORT
      LAYER M5 ;
        RECT  22.896 0 22.92 0.084 ;
    END
  END x_d[26]
  PIN x_d[27]
    DIRECTION OUTPUT ;
    USE SIGNAL ;
    PORT
      LAYER M5 ;
        RECT  23.04 0 23.064 0.084 ;
    END
  END x_d[27]
  PIN x_d[28]
    DIRECTION OUTPUT ;
    USE SIGNAL ;
    PORT
      LAYER M5 ;
        RECT  23.184 0 23.208 0.084 ;
    END
  END x_d[28]
  PIN x_d[29]
    DIRECTION OUTPUT ;
    USE SIGNAL ;
    PORT
      LAYER M5 ;
        RECT  23.328 0 23.352 0.084 ;
    END
  END x_d[29]
  PIN x_d[2]
    DIRECTION OUTPUT ;
    USE SIGNAL ;
    PORT
      LAYER M5 ;
        RECT  19.44 0 19.464 0.084 ;
    END
  END x_d[2]
  PIN x_d[30]
    DIRECTION OUTPUT ;
    USE SIGNAL ;
    PORT
      LAYER M5 ;
        RECT  23.472 0 23.496 0.084 ;
    END
  END x_d[30]
  PIN x_d[31]
    DIRECTION OUTPUT ;
    USE SIGNAL ;
    PORT
      LAYER M5 ;
        RECT  23.616 0 23.64 0.084 ;
    END
  END x_d[31]
  PIN x_d[32]
    DIRECTION OUTPUT ;
    USE SIGNAL ;
    PORT
      LAYER M5 ;
        RECT  29.52 0 29.544 0.084 ;
    END
  END x_d[32]
  PIN x_d[33]
    DIRECTION OUTPUT ;
    USE SIGNAL ;
    PORT
      LAYER M5 ;
        RECT  29.664 0 29.688 0.084 ;
    END
  END x_d[33]
  PIN x_d[34]
    DIRECTION OUTPUT ;
    USE SIGNAL ;
    PORT
      LAYER M5 ;
        RECT  29.808 0 29.832 0.084 ;
    END
  END x_d[34]
  PIN x_d[35]
    DIRECTION OUTPUT ;
    USE SIGNAL ;
    PORT
      LAYER M5 ;
        RECT  29.952 0 29.976 0.084 ;
    END
  END x_d[35]
  PIN x_d[36]
    DIRECTION OUTPUT ;
    USE SIGNAL ;
    PORT
      LAYER M5 ;
        RECT  30.096 0 30.12 0.084 ;
    END
  END x_d[36]
  PIN x_d[37]
    DIRECTION OUTPUT ;
    USE SIGNAL ;
    PORT
      LAYER M5 ;
        RECT  30.24 0 30.264 0.084 ;
    END
  END x_d[37]
  PIN x_d[38]
    DIRECTION OUTPUT ;
    USE SIGNAL ;
    PORT
      LAYER M5 ;
        RECT  30.384 0 30.408 0.084 ;
    END
  END x_d[38]
  PIN x_d[39]
    DIRECTION OUTPUT ;
    USE SIGNAL ;
    PORT
      LAYER M5 ;
        RECT  30.528 0 30.552 0.084 ;
    END
  END x_d[39]
  PIN x_d[3]
    DIRECTION OUTPUT ;
    USE SIGNAL ;
    PORT
      LAYER M5 ;
        RECT  19.584 0 19.608 0.084 ;
    END
  END x_d[3]
  PIN x_d[40]
    DIRECTION OUTPUT ;
    USE SIGNAL ;
    PORT
      LAYER M5 ;
        RECT  30.672 0 30.696 0.084 ;
    END
  END x_d[40]
  PIN x_d[41]
    DIRECTION OUTPUT ;
    USE SIGNAL ;
    PORT
      LAYER M5 ;
        RECT  30.816 0 30.84 0.084 ;
    END
  END x_d[41]
  PIN x_d[42]
    DIRECTION OUTPUT ;
    USE SIGNAL ;
    PORT
      LAYER M5 ;
        RECT  30.96 0 30.984 0.084 ;
    END
  END x_d[42]
  PIN x_d[43]
    DIRECTION OUTPUT ;
    USE SIGNAL ;
    PORT
      LAYER M5 ;
        RECT  31.104 0 31.128 0.084 ;
    END
  END x_d[43]
  PIN x_d[44]
    DIRECTION OUTPUT ;
    USE SIGNAL ;
    PORT
      LAYER M5 ;
        RECT  31.248 0 31.272 0.084 ;
    END
  END x_d[44]
  PIN x_d[45]
    DIRECTION OUTPUT ;
    USE SIGNAL ;
    PORT
      LAYER M5 ;
        RECT  31.392 0 31.416 0.084 ;
    END
  END x_d[45]
  PIN x_d[46]
    DIRECTION OUTPUT ;
    USE SIGNAL ;
    PORT
      LAYER M5 ;
        RECT  31.536 0 31.56 0.084 ;
    END
  END x_d[46]
  PIN x_d[47]
    DIRECTION OUTPUT ;
    USE SIGNAL ;
    PORT
      LAYER M5 ;
        RECT  31.68 0 31.704 0.084 ;
    END
  END x_d[47]
  PIN x_d[48]
    DIRECTION OUTPUT ;
    USE SIGNAL ;
    PORT
      LAYER M5 ;
        RECT  31.824 0 31.848 0.084 ;
    END
  END x_d[48]
  PIN x_d[49]
    DIRECTION OUTPUT ;
    USE SIGNAL ;
    PORT
      LAYER M5 ;
        RECT  31.968 0 31.992 0.084 ;
    END
  END x_d[49]
  PIN x_d[4]
    DIRECTION OUTPUT ;
    USE SIGNAL ;
    PORT
      LAYER M5 ;
        RECT  19.728 0 19.752 0.084 ;
    END
  END x_d[4]
  PIN x_d[50]
    DIRECTION OUTPUT ;
    USE SIGNAL ;
    PORT
      LAYER M5 ;
        RECT  32.112 0 32.136 0.084 ;
    END
  END x_d[50]
  PIN x_d[51]
    DIRECTION OUTPUT ;
    USE SIGNAL ;
    PORT
      LAYER M5 ;
        RECT  32.256 0 32.28 0.084 ;
    END
  END x_d[51]
  PIN x_d[52]
    DIRECTION OUTPUT ;
    USE SIGNAL ;
    PORT
      LAYER M5 ;
        RECT  32.4 0 32.424 0.084 ;
    END
  END x_d[52]
  PIN x_d[53]
    DIRECTION OUTPUT ;
    USE SIGNAL ;
    PORT
      LAYER M5 ;
        RECT  32.544 0 32.568 0.084 ;
    END
  END x_d[53]
  PIN x_d[54]
    DIRECTION OUTPUT ;
    USE SIGNAL ;
    PORT
      LAYER M5 ;
        RECT  32.688 0 32.712 0.084 ;
    END
  END x_d[54]
  PIN x_d[55]
    DIRECTION OUTPUT ;
    USE SIGNAL ;
    PORT
      LAYER M5 ;
        RECT  32.832 0 32.856 0.084 ;
    END
  END x_d[55]
  PIN x_d[56]
    DIRECTION OUTPUT ;
    USE SIGNAL ;
    PORT
      LAYER M5 ;
        RECT  32.976 0 33 0.084 ;
    END
  END x_d[56]
  PIN x_d[57]
    DIRECTION OUTPUT ;
    USE SIGNAL ;
    PORT
      LAYER M5 ;
        RECT  33.12 0 33.144 0.084 ;
    END
  END x_d[57]
  PIN x_d[58]
    DIRECTION OUTPUT ;
    USE SIGNAL ;
    PORT
      LAYER M5 ;
        RECT  33.264 0 33.288 0.084 ;
    END
  END x_d[58]
  PIN x_d[59]
    DIRECTION OUTPUT ;
    USE SIGNAL ;
    PORT
      LAYER M5 ;
        RECT  33.408 0 33.432 0.084 ;
    END
  END x_d[59]
  PIN x_d[5]
    DIRECTION OUTPUT ;
    USE SIGNAL ;
    PORT
      LAYER M5 ;
        RECT  19.872 0 19.896 0.084 ;
    END
  END x_d[5]
  PIN x_d[60]
    DIRECTION OUTPUT ;
    USE SIGNAL ;
    PORT
      LAYER M5 ;
        RECT  33.552 0 33.576 0.084 ;
    END
  END x_d[60]
  PIN x_d[61]
    DIRECTION OUTPUT ;
    USE SIGNAL ;
    PORT
      LAYER M5 ;
        RECT  33.696 0 33.72 0.084 ;
    END
  END x_d[61]
  PIN x_d[62]
    DIRECTION OUTPUT ;
    USE SIGNAL ;
    PORT
      LAYER M5 ;
        RECT  33.84 0 33.864 0.084 ;
    END
  END x_d[62]
  PIN x_d[63]
    DIRECTION OUTPUT ;
    USE SIGNAL ;
    PORT
      LAYER M5 ;
        RECT  33.984 0 34.008 0.084 ;
    END
  END x_d[63]
  PIN x_d[64]
    DIRECTION OUTPUT ;
    USE SIGNAL ;
    PORT
      LAYER M5 ;
        RECT  23.76 0 23.784 0.084 ;
    END
  END x_d[64]
  PIN x_d[65]
    DIRECTION OUTPUT ;
    USE SIGNAL ;
    PORT
      LAYER M5 ;
        RECT  23.904 0 23.928 0.084 ;
    END
  END x_d[65]
  PIN x_d[66]
    DIRECTION OUTPUT ;
    USE SIGNAL ;
    PORT
      LAYER M5 ;
        RECT  24.048 0 24.072 0.084 ;
    END
  END x_d[66]
  PIN x_d[67]
    DIRECTION OUTPUT ;
    USE SIGNAL ;
    PORT
      LAYER M5 ;
        RECT  24.192 0 24.216 0.084 ;
    END
  END x_d[67]
  PIN x_d[68]
    DIRECTION OUTPUT ;
    USE SIGNAL ;
    PORT
      LAYER M5 ;
        RECT  24.336 0 24.36 0.084 ;
    END
  END x_d[68]
  PIN x_d[69]
    DIRECTION OUTPUT ;
    USE SIGNAL ;
    PORT
      LAYER M5 ;
        RECT  24.48 0 24.504 0.084 ;
    END
  END x_d[69]
  PIN x_d[6]
    DIRECTION OUTPUT ;
    USE SIGNAL ;
    PORT
      LAYER M5 ;
        RECT  20.016 0 20.04 0.084 ;
    END
  END x_d[6]
  PIN x_d[70]
    DIRECTION OUTPUT ;
    USE SIGNAL ;
    PORT
      LAYER M5 ;
        RECT  24.624 0 24.648 0.084 ;
    END
  END x_d[70]
  PIN x_d[71]
    DIRECTION OUTPUT ;
    USE SIGNAL ;
    PORT
      LAYER M5 ;
        RECT  24.768 0 24.792 0.084 ;
    END
  END x_d[71]
  PIN x_d[72]
    DIRECTION OUTPUT ;
    USE SIGNAL ;
    PORT
      LAYER M5 ;
        RECT  24.912 0 24.936 0.084 ;
    END
  END x_d[72]
  PIN x_d[73]
    DIRECTION OUTPUT ;
    USE SIGNAL ;
    PORT
      LAYER M5 ;
        RECT  25.056 0 25.08 0.084 ;
    END
  END x_d[73]
  PIN x_d[74]
    DIRECTION OUTPUT ;
    USE SIGNAL ;
    PORT
      LAYER M5 ;
        RECT  25.2 0 25.224 0.084 ;
    END
  END x_d[74]
  PIN x_d[75]
    DIRECTION OUTPUT ;
    USE SIGNAL ;
    PORT
      LAYER M5 ;
        RECT  25.344 0 25.368 0.084 ;
    END
  END x_d[75]
  PIN x_d[76]
    DIRECTION OUTPUT ;
    USE SIGNAL ;
    PORT
      LAYER M5 ;
        RECT  25.488 0 25.512 0.084 ;
    END
  END x_d[76]
  PIN x_d[77]
    DIRECTION OUTPUT ;
    USE SIGNAL ;
    PORT
      LAYER M5 ;
        RECT  25.632 0 25.656 0.084 ;
    END
  END x_d[77]
  PIN x_d[78]
    DIRECTION OUTPUT ;
    USE SIGNAL ;
    PORT
      LAYER M5 ;
        RECT  25.776 0 25.8 0.084 ;
    END
  END x_d[78]
  PIN x_d[79]
    DIRECTION OUTPUT ;
    USE SIGNAL ;
    PORT
      LAYER M5 ;
        RECT  25.92 0 25.944 0.084 ;
    END
  END x_d[79]
  PIN x_d[7]
    DIRECTION OUTPUT ;
    USE SIGNAL ;
    PORT
      LAYER M5 ;
        RECT  20.16 0 20.184 0.084 ;
    END
  END x_d[7]
  PIN x_d[80]
    DIRECTION OUTPUT ;
    USE SIGNAL ;
    PORT
      LAYER M5 ;
        RECT  26.064 0 26.088 0.084 ;
    END
  END x_d[80]
  PIN x_d[81]
    DIRECTION OUTPUT ;
    USE SIGNAL ;
    PORT
      LAYER M5 ;
        RECT  26.208 0 26.232 0.084 ;
    END
  END x_d[81]
  PIN x_d[82]
    DIRECTION OUTPUT ;
    USE SIGNAL ;
    PORT
      LAYER M5 ;
        RECT  26.352 0 26.376 0.084 ;
    END
  END x_d[82]
  PIN x_d[83]
    DIRECTION OUTPUT ;
    USE SIGNAL ;
    PORT
      LAYER M5 ;
        RECT  26.496 0 26.52 0.084 ;
    END
  END x_d[83]
  PIN x_d[84]
    DIRECTION OUTPUT ;
    USE SIGNAL ;
    PORT
      LAYER M5 ;
        RECT  26.64 0 26.664 0.084 ;
    END
  END x_d[84]
  PIN x_d[85]
    DIRECTION OUTPUT ;
    USE SIGNAL ;
    PORT
      LAYER M5 ;
        RECT  26.784 0 26.808 0.084 ;
    END
  END x_d[85]
  PIN x_d[86]
    DIRECTION OUTPUT ;
    USE SIGNAL ;
    PORT
      LAYER M5 ;
        RECT  26.928 0 26.952 0.084 ;
    END
  END x_d[86]
  PIN x_d[87]
    DIRECTION OUTPUT ;
    USE SIGNAL ;
    PORT
      LAYER M5 ;
        RECT  27.072 0 27.096 0.084 ;
    END
  END x_d[87]
  PIN x_d[88]
    DIRECTION OUTPUT ;
    USE SIGNAL ;
    PORT
      LAYER M5 ;
        RECT  27.216 0 27.24 0.084 ;
    END
  END x_d[88]
  PIN x_d[89]
    DIRECTION OUTPUT ;
    USE SIGNAL ;
    PORT
      LAYER M5 ;
        RECT  27.36 0 27.384 0.084 ;
    END
  END x_d[89]
  PIN x_d[8]
    DIRECTION OUTPUT ;
    USE SIGNAL ;
    PORT
      LAYER M5 ;
        RECT  20.304 0 20.328 0.084 ;
    END
  END x_d[8]
  PIN x_d[90]
    DIRECTION OUTPUT ;
    USE SIGNAL ;
    PORT
      LAYER M5 ;
        RECT  27.504 0 27.528 0.084 ;
    END
  END x_d[90]
  PIN x_d[91]
    DIRECTION OUTPUT ;
    USE SIGNAL ;
    PORT
      LAYER M5 ;
        RECT  27.648 0 27.672 0.084 ;
    END
  END x_d[91]
  PIN x_d[92]
    DIRECTION OUTPUT ;
    USE SIGNAL ;
    PORT
      LAYER M5 ;
        RECT  27.792 0 27.816 0.084 ;
    END
  END x_d[92]
  PIN x_d[93]
    DIRECTION OUTPUT ;
    USE SIGNAL ;
    PORT
      LAYER M5 ;
        RECT  27.936 0 27.96 0.084 ;
    END
  END x_d[93]
  PIN x_d[94]
    DIRECTION OUTPUT ;
    USE SIGNAL ;
    PORT
      LAYER M5 ;
        RECT  28.08 0 28.104 0.084 ;
    END
  END x_d[94]
  PIN x_d[95]
    DIRECTION OUTPUT ;
    USE SIGNAL ;
    PORT
      LAYER M5 ;
        RECT  28.224 0 28.248 0.084 ;
    END
  END x_d[95]
  PIN x_d[96]
    DIRECTION OUTPUT ;
    USE SIGNAL ;
    PORT
      LAYER M5 ;
        RECT  14.544 0 14.568 0.084 ;
    END
  END x_d[96]
  PIN x_d[97]
    DIRECTION OUTPUT ;
    USE SIGNAL ;
    PORT
      LAYER M5 ;
        RECT  14.688 0 14.712 0.084 ;
    END
  END x_d[97]
  PIN x_d[98]
    DIRECTION OUTPUT ;
    USE SIGNAL ;
    PORT
      LAYER M5 ;
        RECT  14.832 0 14.856 0.084 ;
    END
  END x_d[98]
  PIN x_d[99]
    DIRECTION OUTPUT ;
    USE SIGNAL ;
    PORT
      LAYER M5 ;
        RECT  14.976 0 15 0.084 ;
    END
  END x_d[99]
  PIN x_d[9]
    DIRECTION OUTPUT ;
    USE SIGNAL ;
    PORT
      LAYER M5 ;
        RECT  20.448 0 20.472 0.084 ;
    END
  END x_d[9]
  PIN VDD
    DIRECTION INOUT ;
    USE POWER ;
    PORT
      LAYER M5 ;
        RECT  40.392 2.151 40.512 19.449 ;
        RECT  37.692 2.151 37.812 19.449 ;
        RECT  34.992 2.151 35.112 19.449 ;
        RECT  32.292 2.151 32.412 19.449 ;
        RECT  29.592 2.151 29.712 19.449 ;
        RECT  26.892 2.151 27.012 19.449 ;
        RECT  24.192 2.151 24.312 19.449 ;
        RECT  21.492 2.151 21.612 19.449 ;
        RECT  18.792 2.151 18.912 19.449 ;
        RECT  16.092 2.151 16.212 19.449 ;
        RECT  13.392 2.151 13.512 19.449 ;
        RECT  10.692 2.151 10.812 19.449 ;
        RECT  7.992 2.151 8.112 19.449 ;
        RECT  5.292 2.151 5.412 19.449 ;
        RECT  2.592 2.151 2.712 19.449 ;
    END
  END VDD
  PIN VSS
    DIRECTION INOUT ;
    USE GROUND ;
    PORT
      LAYER M5 ;
        RECT  40.2 2.137 40.32 19.463 ;
        RECT  37.5 2.137 37.62 19.463 ;
        RECT  34.8 2.137 34.92 19.463 ;
        RECT  32.1 2.137 32.22 19.463 ;
        RECT  29.4 2.137 29.52 19.463 ;
        RECT  26.7 2.137 26.82 19.463 ;
        RECT  24 2.137 24.12 19.463 ;
        RECT  21.3 2.137 21.42 19.463 ;
        RECT  18.6 2.137 18.72 19.463 ;
        RECT  15.9 2.137 16.02 19.463 ;
        RECT  13.2 2.137 13.32 19.463 ;
        RECT  10.5 2.137 10.62 19.463 ;
        RECT  7.8 2.137 7.92 19.463 ;
        RECT  5.1 2.137 5.22 19.463 ;
        RECT  2.4 2.137 2.52 19.463 ;
    END
  END VSS
  # OT_OBS_CLOSED layer=M5 d_um=1.536 added=50
  OBS
    LAYER RVTN ;
     RECT  2.16 2.16 41.04 2.295 ;
     RECT  2.16 2.565 41.04 2.835 ;
     RECT  2.16 3.105 41.04 3.375 ;
     RECT  2.16 3.645 41.04 3.915 ;
     RECT  2.16 4.185 41.04 4.455 ;
     RECT  2.16 4.725 41.04 4.995 ;
     RECT  2.16 5.265 41.04 5.535 ;
     RECT  2.16 5.805 41.04 6.075 ;
     RECT  2.16 6.345 41.04 6.615 ;
     RECT  2.16 6.885 41.04 7.155 ;
     RECT  2.16 7.425 41.04 7.695 ;
     RECT  2.16 7.965 41.04 8.235 ;
     RECT  2.16 8.505 41.04 8.775 ;
     RECT  2.16 9.045 41.04 9.315 ;
     RECT  2.16 9.585 41.04 9.855 ;
     RECT  2.16 10.125 41.04 10.395 ;
     RECT  2.16 10.665 41.04 10.935 ;
     RECT  2.16 11.205 41.04 11.475 ;
     RECT  2.16 11.745 41.04 12.015 ;
     RECT  2.16 12.285 41.04 12.555 ;
     RECT  2.16 12.825 41.04 13.095 ;
     RECT  2.16 13.365 41.04 13.635 ;
     RECT  2.16 13.905 41.04 14.175 ;
     RECT  2.16 14.445 41.04 14.715 ;
     RECT  2.16 14.985 41.04 15.255 ;
     RECT  2.16 15.525 41.04 15.795 ;
     RECT  2.16 16.065 41.04 16.335 ;
     RECT  2.16 16.605 41.04 16.875 ;
     RECT  2.16 17.145 41.04 17.415 ;
     RECT  2.16 17.685 41.04 17.955 ;
     RECT  2.16 18.225 41.04 18.495 ;
     RECT  2.16 18.765 41.04 19.035 ;
     RECT  2.16 19.305 41.04 19.44 ;
    LAYER RVTP ;
     RECT  2.16 2.295 41.04 2.565 ;
     RECT  2.16 2.835 41.04 3.105 ;
     RECT  2.16 3.375 41.04 3.645 ;
     RECT  2.16 3.915 41.04 4.185 ;
     RECT  2.16 4.455 41.04 4.725 ;
     RECT  2.16 4.995 41.04 5.265 ;
     RECT  2.16 5.535 41.04 5.805 ;
     RECT  2.16 6.075 41.04 6.345 ;
     RECT  2.16 6.615 41.04 6.885 ;
     RECT  2.16 7.155 41.04 7.425 ;
     RECT  2.16 7.695 41.04 7.965 ;
     RECT  2.16 8.235 41.04 8.505 ;
     RECT  2.16 8.775 41.04 9.045 ;
     RECT  2.16 9.315 41.04 9.585 ;
     RECT  2.16 9.855 41.04 10.125 ;
     RECT  2.16 10.395 41.04 10.665 ;
     RECT  2.16 10.935 41.04 11.205 ;
     RECT  2.16 11.475 41.04 11.745 ;
     RECT  2.16 12.015 41.04 12.285 ;
     RECT  2.16 12.555 41.04 12.825 ;
     RECT  2.16 13.095 41.04 13.365 ;
     RECT  2.16 13.635 41.04 13.905 ;
     RECT  2.16 14.175 41.04 14.445 ;
     RECT  2.16 14.715 41.04 14.985 ;
     RECT  2.16 15.255 41.04 15.525 ;
     RECT  2.16 15.795 41.04 16.065 ;
     RECT  2.16 16.335 41.04 16.605 ;
     RECT  2.16 16.875 41.04 17.145 ;
     RECT  2.16 17.415 41.04 17.685 ;
     RECT  2.16 17.955 41.04 18.225 ;
     RECT  2.16 18.495 41.04 18.765 ;
     RECT  2.16 19.035 41.04 19.305 ;
    LAYER M1 ;
     RECT  2.16 2.151 41.04 19.449 ;
    LAYER M2 ;
     RECT  18.427 1.152 18.563 1.17 ;
     RECT  20.407 1.152 20.507 1.17 ;
     RECT  2.16 2.151 22.027 19.449 ;
     RECT  22.027 2.106 23.287 19.449 ;
     RECT  23.287 2.034 24.647 19.449 ;
     RECT  24.647 2.151 25.519 19.449 ;
     RECT  25.519 2.106 26.915 19.449 ;
     RECT  27.607 1.152 27.887 1.17 ;
     RECT  26.915 2.151 29.659 19.449 ;
     RECT  29.659 2.106 30.047 19.449 ;
     RECT  30.047 2.151 31.027 19.449 ;
     RECT  31.027 2.106 32.675 19.449 ;
     RECT  32.675 2.151 41.04 19.449 ;
     RECT  41.04 17.964 41.387 19.296 ;
     RECT  41.387 18.126 41.639 19.296 ;
     RECT  41.639 18.126 41.675 19.224 ;
     RECT  41.675 18.504 41.711 19.224 ;
     RECT  41.711 18.504 41.819 19.026 ;
     RECT  41.819 18.576 42.215 19.026 ;
     RECT  42.215 18.576 42.251 18.594 ;
    LAYER M3 ;
     RECT  32.256 0.091 32.274 0.139 ;
     RECT  20.124 0.571 20.142 0.619 ;
     RECT  27.9 0.571 27.918 1.099 ;
     RECT  14.22 1.099 14.238 1.147 ;
     RECT  15.084 0.571 15.102 1.147 ;
     RECT  18.54 0.091 18.558 1.147 ;
     RECT  20.124 0.619 20.43 1.147 ;
     RECT  27.612 1.099 27.918 1.147 ;
     RECT  31.14 0.571 31.158 1.147 ;
     RECT  30.6 1.147 31.158 1.195 ;
     RECT  14.22 1.147 15.102 1.627 ;
     RECT  15.84 1.099 15.858 1.627 ;
     RECT  18.432 1.147 18.558 1.723 ;
     RECT  27.288 1.147 27.918 1.723 ;
     RECT  30.528 1.195 31.158 1.723 ;
     RECT  27.288 1.723 28.242 1.771 ;
     RECT  32.256 0.139 32.49 1.771 ;
     RECT  34.02 1.723 34.038 1.771 ;
     RECT  21.276 1.723 21.294 2.011 ;
     RECT  22.572 1.723 22.59 2.029 ;
     RECT  23.976 1.675 23.994 2.029 ;
     RECT  22.572 2.029 24.642 2.101 ;
     RECT  29.952 1.723 31.194 2.101 ;
     RECT  14.22 1.627 15.858 2.143 ;
     RECT  21.24 2.011 21.294 2.143 ;
     RECT  22.032 2.101 24.642 2.143 ;
     RECT  29.664 2.101 31.194 2.143 ;
     RECT  32.256 1.771 33.03 2.143 ;
     RECT  34.02 1.771 34.146 2.143 ;
     RECT  35.244 1.819 35.262 2.143 ;
     RECT  16.848 1.723 16.866 2.155 ;
     RECT  16.848 2.155 16.902 2.191 ;
     RECT  18.36 1.723 19.242 2.191 ;
     RECT  20.124 1.147 20.502 2.191 ;
     RECT  21.24 2.143 24.642 2.191 ;
     RECT  25.524 2.101 25.542 2.191 ;
     RECT  26.64 1.771 28.422 2.191 ;
     RECT  29.415 2.143 31.194 2.191 ;
     RECT  32.115 2.143 33.03 2.191 ;
     RECT  34.02 2.143 35.262 2.191 ;
     RECT  36 2.059 36.018 2.191 ;
     RECT  33.876 2.191 36.018 2.219 ;
     RECT  29.415 2.191 33.03 2.263 ;
     RECT  33.876 2.219 35.766 2.263 ;
     RECT  29.415 2.263 35.766 2.299 ;
     RECT  14.22 2.143 16.005 2.371 ;
     RECT  16.848 2.191 17.442 2.371 ;
     RECT  18.36 2.191 28.422 2.371 ;
     RECT  29.16 2.299 35.766 2.371 ;
     RECT  2.415 2.143 2.505 2.413 ;
     RECT  5.115 2.143 5.205 2.413 ;
     RECT  7.815 2.143 7.905 2.413 ;
     RECT  10.515 2.143 10.605 2.413 ;
     RECT  13.215 2.143 13.305 2.413 ;
     RECT  37.515 2.143 37.605 2.413 ;
     RECT  40.215 2.143 40.305 2.413 ;
     RECT  13.215 2.413 13.497 2.569 ;
     RECT  14.22 2.371 17.442 2.569 ;
     RECT  13.215 2.569 17.442 2.641 ;
     RECT  18.36 2.371 35.766 2.641 ;
     RECT  13.215 2.641 35.766 3.029 ;
     RECT  13.215 3.029 35.622 3.065 ;
     RECT  13.215 3.065 35.334 3.749 ;
     RECT  13.215 3.749 35.262 4.919 ;
     RECT  13.215 4.919 35.226 4.963 ;
     RECT  5.115 2.413 5.397 5.773 ;
     RECT  12.816 4.963 35.226 5.845 ;
     RECT  12.276 5.845 35.226 6.007 ;
     RECT  6.624 4.927 6.642 6.313 ;
     RECT  10.515 2.413 10.797 6.313 ;
     RECT  7.815 2.413 8.097 6.853 ;
     RECT  7.815 6.853 8.658 7.465 ;
     RECT  9.54 7.231 9.558 7.465 ;
     RECT  10.515 6.313 10.854 7.501 ;
     RECT  12.276 6.007 35.622 7.735 ;
     RECT  7.815 7.465 9.558 7.771 ;
     RECT  10.515 7.501 10.926 7.771 ;
     RECT  7.815 7.771 10.926 8.041 ;
     RECT  37.515 2.413 37.797 8.743 ;
     RECT  12.276 7.735 36.234 9.391 ;
     RECT  37.296 8.743 37.797 9.391 ;
     RECT  12.276 9.391 37.797 11.785 ;
     RECT  12.132 11.785 37.797 12.217 ;
     RECT  12.132 12.217 37.854 12.829 ;
     RECT  7.815 8.041 11.106 13.027 ;
     RECT  12.06 12.829 37.854 13.027 ;
     RECT  6.624 6.313 6.93 17.419 ;
     RECT  7.815 13.027 37.854 17.419 ;
     RECT  5.115 5.773 5.85 17.455 ;
     RECT  6.624 17.419 37.854 17.455 ;
     RECT  40.215 2.413 40.497 17.491 ;
     RECT  38.592 17.383 38.61 17.725 ;
     RECT  39.636 17.491 40.497 17.725 ;
     RECT  5.115 17.455 37.854 17.995 ;
     RECT  38.592 17.725 40.497 17.995 ;
     RECT  41.364 17.959 41.382 18.121 ;
     RECT  5.115 17.995 40.497 18.475 ;
     RECT  41.364 18.121 41.67 18.475 ;
     RECT  5.115 18.475 41.67 18.499 ;
     RECT  5.115 18.499 41.814 18.535 ;
     RECT  4.536 18.535 41.814 18.571 ;
     RECT  2.415 2.413 2.697 19.187 ;
     RECT  4.536 18.571 42.246 19.229 ;
     RECT  4.536 19.229 17.73 19.301 ;
     RECT  4.536 19.301 13.554 19.373 ;
     RECT  14.292 19.301 17.73 19.373 ;
     RECT  18.576 19.229 42.246 19.373 ;
     RECT  20.268 19.373 20.286 19.379 ;
     RECT  21.24 19.373 24.498 19.379 ;
     RECT  14.76 19.373 14.778 19.409 ;
     RECT  15.915 19.373 17.73 19.409 ;
     RECT  30.672 19.373 42.246 19.409 ;
     RECT  10.26 19.373 10.854 19.421 ;
     RECT  15.915 19.409 17.046 19.421 ;
     RECT  21.24 19.379 22.086 19.421 ;
     RECT  2.415 19.187 2.505 19.457 ;
     RECT  7.815 19.373 8.118 19.457 ;
     RECT  13.215 19.373 13.446 19.457 ;
     RECT  15.915 19.421 16.47 19.457 ;
     RECT  18.576 19.373 18.705 19.457 ;
     RECT  32.076 19.409 42.246 19.457 ;
     RECT  4.716 19.373 5.706 19.565 ;
     RECT  10.476 19.421 10.854 19.565 ;
     RECT  13.356 19.457 13.446 19.565 ;
     RECT  16.056 19.457 16.47 19.565 ;
     RECT  29.376 19.373 29.754 19.565 ;
     RECT  35.568 19.457 42.246 19.565 ;
     RECT  4.716 19.565 5.598 19.613 ;
     RECT  7.956 19.457 8.118 19.613 ;
     RECT  10.476 19.565 10.494 19.613 ;
     RECT  13.356 19.565 13.374 19.613 ;
     RECT  16.056 19.565 16.074 19.613 ;
     RECT  18.576 19.457 18.594 19.613 ;
     RECT  29.376 19.565 29.61 19.613 ;
     RECT  32.076 19.457 34.506 19.613 ;
     RECT  5.58 19.613 5.598 19.661 ;
     RECT  8.1 19.613 8.118 19.661 ;
     RECT  30.672 19.409 31.302 19.661 ;
     RECT  21.24 19.421 21.762 19.709 ;
     RECT  23.292 19.379 24.498 19.997 ;
     RECT  25.956 19.373 27.198 19.997 ;
     RECT  35.568 19.565 37.206 20.045 ;
     RECT  36.756 20.045 37.206 20.141 ;
     RECT  32.508 19.613 34.506 20.237 ;
     RECT  33.192 20.237 34.506 20.477 ;
     RECT  21.744 19.709 21.762 20.573 ;
     RECT  23.292 19.997 23.31 20.573 ;
     RECT  27.18 19.997 27.198 20.573 ;
     RECT  35.568 20.045 35.586 20.573 ;
     RECT  37.188 20.141 37.206 20.573 ;
     RECT  38.16 19.565 42.246 20.573 ;
     RECT  38.196 20.573 40.374 20.669 ;
     RECT  41.112 20.573 42.246 20.669 ;
     RECT  33.588 20.477 34.506 20.717 ;
     RECT  33.588 20.717 33.966 21.451 ;
     RECT  4.716 19.613 4.734 21.485 ;
     RECT  25.956 19.997 25.974 21.485 ;
     RECT  33.408 21.451 33.966 21.485 ;
     RECT  38.628 20.669 40.374 21.485 ;
     RECT  41.364 20.669 42.246 21.485 ;
     RECT  30.672 19.661 30.69 21.581 ;
     RECT  33.408 21.485 33.426 21.581 ;
    LAYER M4 ;
     RECT  2.408 2.148 2.512 19.452 ;
     RECT  2.512 2.418 2.704 19.182 ;
     RECT  4.165 18.432 4.453 18.456 ;
     RECT  4.309 21.456 4.745 21.48 ;
     RECT  4.453 18.432 4.988 19.368 ;
     RECT  4.988 18.432 5.108 19.608 ;
     RECT  5.108 2.148 5.212 19.608 ;
     RECT  5.212 2.418 5.404 19.608 ;
     RECT  5.404 18.432 5.461 19.608 ;
     RECT  5.461 18.432 5.609 19.656 ;
     RECT  5.609 18.432 5.717 19.56 ;
     RECT  5.717 18.432 7.045 19.368 ;
     RECT  7.045 18.24 7.765 19.368 ;
     RECT  7.765 18.24 7.808 19.608 ;
     RECT  7.808 2.148 7.909 19.608 ;
     RECT  7.909 2.148 7.912 19.656 ;
     RECT  7.912 2.418 8.104 19.656 ;
     RECT  8.104 18.24 8.129 19.656 ;
     RECT  8.053 21.264 8.197 21.288 ;
     RECT  8.197 21.264 8.243 21.384 ;
     RECT  8.243 21.36 8.339 21.384 ;
     RECT  8.129 18.24 10.069 19.368 ;
     RECT  10.069 18.24 10.213 19.416 ;
     RECT  10.213 18.192 10.309 19.416 ;
     RECT  10.309 18.192 10.508 19.656 ;
     RECT  10.508 2.148 10.612 19.656 ;
     RECT  10.645 21.408 10.787 21.432 ;
     RECT  10.612 2.418 10.804 19.656 ;
     RECT  10.804 17.712 10.835 19.656 ;
     RECT  10.835 17.712 10.865 19.56 ;
     RECT  10.865 17.712 11.333 19.368 ;
     RECT  11.333 18.24 12.625 19.368 ;
     RECT  12.625 18.096 13.208 19.368 ;
     RECT  13.208 2.148 13.237 19.452 ;
     RECT  13.237 2.148 13.312 19.608 ;
     RECT  13.312 2.418 13.385 19.608 ;
     RECT  13.385 2.418 13.457 19.56 ;
     RECT  13.457 2.418 13.504 19.368 ;
     RECT  13.504 18.24 13.565 19.368 ;
     RECT  13.525 21.456 13.667 21.48 ;
     RECT  14.209 1.104 14.425 1.128 ;
     RECT  14.497 10.752 14.645 10.776 ;
     RECT  13.504 7.632 14.732 7.656 ;
     RECT  14.732 7.632 14.741 8.184 ;
     RECT  14.425 1.104 14.924 1.752 ;
     RECT  14.741 7.632 14.972 8.28 ;
     RECT  14.972 7.584 15.013 8.28 ;
     RECT  14.924 1.104 15.073 2.28 ;
     RECT  15.073 0.576 15.217 2.28 ;
     RECT  13.565 18.432 15.253 19.368 ;
     RECT  14.749 5.568 15.349 5.592 ;
     RECT  15.349 5.232 15.548 5.592 ;
     RECT  15.548 5.04 15.577 5.592 ;
     RECT  15.013 6.816 15.577 8.28 ;
     RECT  15.577 5.04 15.721 8.28 ;
     RECT  15.253 18.24 15.733 19.368 ;
     RECT  15.217 0.576 15.908 2.904 ;
     RECT  15.721 5.04 15.908 8.568 ;
     RECT  14.965 10.8 15.908 10.824 ;
     RECT  15.733 18.24 15.908 19.608 ;
     RECT  15.908 0.576 16.019 19.608 ;
     RECT  16.019 1.728 16.085 19.608 ;
     RECT  16.085 1.728 16.204 19.56 ;
     RECT  16.117 0.144 16.355 0.264 ;
     RECT  16.117 21.408 16.355 21.432 ;
     RECT  16.355 0.24 16.403 0.264 ;
     RECT  16.204 1.728 16.451 4.584 ;
     RECT  16.204 18.24 16.481 19.56 ;
     RECT  16.204 5.568 16.661 8.568 ;
     RECT  16.481 18.24 17.057 19.416 ;
     RECT  16.451 1.728 17.171 2.904 ;
     RECT  16.661 6.288 17.317 8.568 ;
     RECT  17.317 6.288 17.363 9 ;
     RECT  17.171 2.88 17.453 2.904 ;
     RECT  16.451 3.984 17.549 4.584 ;
     RECT  17.363 7.392 17.557 9 ;
     RECT  17.549 3.408 17.756 4.584 ;
     RECT  17.171 1.728 18.277 1.752 ;
     RECT  17.756 3.408 18.373 4.92 ;
     RECT  17.363 6.288 18.373 6.312 ;
     RECT  18.373 3.408 18.421 6.312 ;
     RECT  18.421 0.096 18.469 0.12 ;
     RECT  17.057 18.24 18.469 19.368 ;
     RECT  18.469 18.24 18.565 19.656 ;
     RECT  18.469 0.096 18.569 0.216 ;
     RECT  18.277 1.728 18.608 2.328 ;
     RECT  18.421 3.312 18.608 6.312 ;
     RECT  17.557 7.392 18.608 9.192 ;
     RECT  18.565 18 18.608 19.656 ;
     RECT  18.569 0.144 18.611 0.216 ;
     RECT  18.608 1.728 18.755 19.656 ;
     RECT  18.755 1.728 18.904 19.368 ;
     RECT  18.853 21.264 18.997 21.288 ;
     RECT  18.904 3.408 19.001 7.944 ;
     RECT  18.997 21.264 19.043 21.384 ;
     RECT  18.611 0.144 19.091 0.168 ;
     RECT  19.043 21.36 19.139 21.384 ;
     RECT  18.904 1.728 19.253 2.28 ;
     RECT  18.904 18.432 19.433 19.368 ;
     RECT  19.433 18.528 19.721 19.368 ;
     RECT  19.933 14.736 20.005 14.76 ;
     RECT  18.904 12.336 20.045 12.408 ;
     RECT  19.001 3.984 20.113 5.16 ;
     RECT  20.005 0.576 20.149 0.6 ;
     RECT  20.005 14.736 20.189 14.856 ;
     RECT  20.113 3.648 20.197 5.16 ;
     RECT  20.149 0.576 20.441 0.648 ;
     RECT  19.001 6.288 20.653 7.944 ;
     RECT  18.904 8.976 20.653 9 ;
     RECT  19.253 2.256 20.725 2.28 ;
     RECT  20.725 2.256 20.869 2.328 ;
     RECT  20.197 3.408 20.869 5.16 ;
     RECT  20.869 2.256 21.013 5.16 ;
     RECT  20.653 6.288 21.013 9 ;
     RECT  21.013 2.256 21.157 9 ;
     RECT  20.189 14.736 21.193 14.76 ;
     RECT  19.721 18.672 21.229 19.368 ;
     RECT  21.157 1.728 21.308 9 ;
     RECT  20.045 12.384 21.308 12.408 ;
     RECT  21.193 13.872 21.308 14.76 ;
     RECT  21.109 15.84 21.308 15.864 ;
     RECT  21.229 18.672 21.308 19.704 ;
     RECT  21.109 0.144 21.347 0.168 ;
     RECT  21.308 1.728 21.491 19.704 ;
     RECT  21.491 1.728 21.604 19.56 ;
     RECT  21.604 13.152 21.629 13.32 ;
     RECT  21.604 1.728 21.635 2.04 ;
     RECT  21.604 19.104 21.665 19.56 ;
     RECT  21.692 20.544 21.779 20.568 ;
     RECT  21.604 7.44 22.211 8.568 ;
     RECT  21.604 3.984 22.313 6.12 ;
     RECT  21.665 19.104 22.355 19.416 ;
     RECT  21.635 1.728 22.601 1.752 ;
     RECT  22.355 19.104 22.813 19.368 ;
     RECT  22.813 18.816 23.353 19.368 ;
     RECT  22.313 3.984 23.468 5.16 ;
     RECT  23.281 20.544 23.507 20.568 ;
     RECT  23.468 3.936 23.509 5.16 ;
     RECT  23.509 3.552 23.749 5.16 ;
     RECT  23.353 18.672 23.749 19.368 ;
     RECT  22.211 7.44 23.857 7.848 ;
     RECT  23.221 1.152 23.965 1.176 ;
     RECT  23.093 2.256 23.965 2.28 ;
     RECT  23.965 1.152 24.008 2.28 ;
     RECT  23.749 3.408 24.008 5.16 ;
     RECT  23.857 7.392 24.008 7.848 ;
     RECT  23.749 18.672 24.008 19.992 ;
     RECT  24.008 1.152 24.112 19.992 ;
     RECT  24.112 2.418 24.304 19.992 ;
     RECT  24.181 0.144 24.325 0.168 ;
     RECT  24.112 1.152 24.325 1.272 ;
     RECT  24.325 0.144 24.419 1.272 ;
     RECT  24.181 21.408 24.419 21.432 ;
     RECT  24.419 0.24 24.467 1.272 ;
     RECT  24.304 2.418 24.517 5.832 ;
     RECT  24.304 18.72 24.803 19.992 ;
     RECT  24.467 1.152 25.091 1.272 ;
     RECT  24.517 2.418 25.117 5.256 ;
     RECT  24.304 7.392 25.297 8.712 ;
     RECT  24.803 18.72 25.405 19.368 ;
     RECT  25.297 6.864 25.517 8.712 ;
     RECT  25.117 2.208 25.571 5.256 ;
     RECT  25.571 2.208 25.667 2.904 ;
     RECT  25.657 16.32 25.729 16.344 ;
     RECT  25.571 3.984 26.045 5.256 ;
     RECT  26.045 3.984 26.101 5.736 ;
     RECT  25.091 1.152 26.195 1.176 ;
     RECT  25.405 18.624 26.377 19.368 ;
     RECT  25.945 21.456 26.387 21.48 ;
     RECT  26.377 18.432 26.588 19.368 ;
     RECT  26.588 18.432 26.593 19.608 ;
     RECT  26.197 1.728 26.629 1.752 ;
     RECT  25.667 2.832 26.629 2.904 ;
     RECT  26.101 3.984 26.629 5.976 ;
     RECT  26.593 18.432 26.701 19.992 ;
     RECT  26.629 1.728 26.708 1.8 ;
     RECT  26.629 2.832 26.708 5.976 ;
     RECT  25.517 7.392 26.708 8.712 ;
     RECT  25.729 15.792 26.708 16.344 ;
     RECT  26.701 18.24 26.708 19.992 ;
     RECT  26.708 1.728 26.819 19.992 ;
     RECT  26.773 0.144 26.917 0.168 ;
     RECT  26.819 1.728 27.004 19.56 ;
     RECT  27.004 16.08 27.145 19.56 ;
     RECT  26.917 0.144 27.277 0.36 ;
     RECT  27.004 1.728 27.277 4.68 ;
     RECT  27.277 0.144 27.347 4.68 ;
     RECT  27.169 20.544 27.395 20.568 ;
     RECT  27.347 0.576 27.683 2.328 ;
     RECT  27.683 0.576 27.929 0.6 ;
     RECT  27.004 6.24 27.965 8.232 ;
     RECT  27.347 3.408 28.001 4.68 ;
     RECT  27.145 16.08 28.001 19.368 ;
     RECT  27.997 10.8 28.109 10.824 ;
     RECT  27.683 1.728 28.253 2.328 ;
     RECT  28.033 4.992 28.253 5.016 ;
     RECT  28.001 3.408 28.289 3.432 ;
     RECT  28.253 1.776 28.433 2.328 ;
     RECT  28.433 2.304 29.269 2.328 ;
     RECT  28.001 16.896 29.365 19.368 ;
     RECT  29.269 2.304 29.408 3.048 ;
     RECT  27.965 6.816 29.408 8.232 ;
     RECT  29.365 16.896 29.408 19.608 ;
     RECT  29.269 0.096 29.555 0.12 ;
     RECT  29.408 2.148 29.621 19.608 ;
     RECT  29.621 2.148 29.704 19.56 ;
     RECT  29.704 17.136 29.765 19.56 ;
     RECT  29.765 17.136 29.873 19.368 ;
     RECT  29.704 2.148 29.893 2.28 ;
     RECT  29.653 0.192 29.939 0.312 ;
     RECT  29.893 1.728 30.229 2.28 ;
     RECT  30.229 0.576 30.563 2.28 ;
     RECT  29.704 5.424 30.563 8.712 ;
     RECT  30.563 0.576 30.629 1.752 ;
     RECT  30.563 5.424 30.809 8.232 ;
     RECT  29.704 3.408 30.908 3.432 ;
     RECT  30.908 2.88 31.093 3.432 ;
     RECT  30.629 0.576 31.169 0.6 ;
     RECT  29.873 18.24 31.273 19.368 ;
     RECT  29.873 17.136 31.309 17.16 ;
     RECT  31.273 18.24 31.309 19.656 ;
     RECT  31.093 2.88 31.492 4.008 ;
     RECT  31.492 2.88 31.669 4.056 ;
     RECT  31.669 2.88 31.741 4.152 ;
     RECT  30.809 7.056 31.885 8.232 ;
     RECT  30.661 21.552 31.909 21.576 ;
     RECT  31.309 17.136 31.916 19.656 ;
     RECT  31.885 6.768 31.921 8.232 ;
     RECT  31.741 2.832 31.949 4.152 ;
     RECT  30.629 1.728 32.108 1.752 ;
     RECT  31.949 2.832 32.108 4.2 ;
     RECT  30.809 5.424 32.108 5.688 ;
     RECT  31.921 6.768 32.108 8.808 ;
     RECT  31.949 10.512 32.108 10.536 ;
     RECT  31.993 11.712 32.108 11.736 ;
     RECT  32.029 14.832 32.108 14.856 ;
     RECT  31.916 17.088 32.108 19.656 ;
     RECT  31.957 0.096 32.285 0.312 ;
     RECT  31.909 21.408 32.291 21.576 ;
     RECT  32.108 1.728 32.404 19.656 ;
     RECT  32.285 0.144 32.435 0.312 ;
     RECT  32.404 17.328 32.497 19.656 ;
     RECT  32.435 0.144 32.501 0.168 ;
     RECT  32.497 17.328 32.531 20.232 ;
     RECT  32.531 17.424 32.537 20.232 ;
     RECT  32.404 2.832 32.545 4.248 ;
     RECT  32.404 11.808 32.545 12.024 ;
     RECT  32.404 5.52 32.627 8.808 ;
     RECT  32.627 5.52 32.717 7.704 ;
     RECT  32.717 5.52 32.789 5.88 ;
     RECT  32.789 5.664 32.819 5.88 ;
     RECT  32.545 12 32.833 12.024 ;
     RECT  32.717 7.68 32.915 7.704 ;
     RECT  32.545 2.832 32.933 4.2 ;
     RECT  32.537 17.616 33.181 20.232 ;
     RECT  32.933 2.832 33.221 4.152 ;
     RECT  33.181 17.616 33.293 20.472 ;
     RECT  32.404 1.728 33.397 1.8 ;
     RECT  33.221 2.832 33.397 4.008 ;
     RECT  32.291 21.552 33.397 21.576 ;
     RECT  33.397 1.728 33.401 4.008 ;
     RECT  33.397 21.456 33.437 21.576 ;
     RECT  32.627 8.784 33.725 8.808 ;
     RECT  33.293 18.096 33.965 20.472 ;
     RECT  33.437 21.456 33.965 21.48 ;
     RECT  32.819 5.664 34.045 5.688 ;
     RECT  33.401 1.728 34.049 3.576 ;
     RECT  34.049 1.776 34.157 3.576 ;
     RECT  33.965 18.096 34.739 21.48 ;
     RECT  34.157 1.824 34.808 3.576 ;
     RECT  34.045 5.136 34.808 5.688 ;
     RECT  34.739 18.096 34.808 20.712 ;
     RECT  34.808 1.824 35.104 20.712 ;
     RECT  35.104 18.24 35.171 20.712 ;
     RECT  35.104 1.824 35.273 2.328 ;
     RECT  35.273 2.064 35.777 2.328 ;
     RECT  35.777 2.064 36.029 2.088 ;
     RECT  35.171 18.24 37.508 20.568 ;
     RECT  37.508 2.148 37.612 20.568 ;
     RECT  37.612 2.418 37.804 20.568 ;
     RECT  37.804 18.432 38.185 20.568 ;
     RECT  38.185 18.432 38.573 20.664 ;
     RECT  38.573 18.432 39.203 21.48 ;
     RECT  39.203 20.544 39.347 21.48 ;
     RECT  39.203 18.432 40.208 19.56 ;
     RECT  40.208 2.148 40.312 19.56 ;
     RECT  39.347 20.592 40.412 21.48 ;
     RECT  40.312 2.418 40.504 19.56 ;
     RECT  40.504 18.48 40.643 19.56 ;
     RECT  40.643 18.48 40.853 19.416 ;
     RECT  40.853 19.344 40.931 19.416 ;
     RECT  40.931 19.392 41.075 19.416 ;
     RECT  40.412 20.544 42.257 21.48 ;
     RECT  42.257 20.544 42.371 20.568 ;
    LAYER M5 ;
     RECT  29.544 0.016 29.664 0.084 ;
     RECT  29.688 0.016 29.808 0.084 ;
     RECT  29.832 0.016 29.952 0.084 ;
     RECT  29.976 0.016 30.096 0.084 ;
     RECT  30.12 0.016 30.24 0.084 ;
     RECT  30.264 0.016 30.384 0.084 ;
     RECT  30.408 0.016 30.528 0.084 ;
     RECT  30.552 0.016 30.672 0.084 ;
     RECT  30.696 0.016 30.816 0.084 ;
     RECT  30.84 0.016 30.96 0.084 ;
     RECT  30.984 0.016 31.104 0.084 ;
     RECT  31.128 0.016 31.248 0.084 ;
     RECT  31.272 0.016 31.392 0.084 ;
     RECT  31.416 0.016 31.536 0.084 ;
     RECT  31.56 0.016 31.68 0.084 ;
     RECT  31.704 0.016 31.824 0.084 ;
     RECT  31.848 0.016 31.968 0.084 ;
     RECT  31.992 0.016 32.112 0.084 ;
     RECT  32.136 0.016 32.256 0.084 ;
     RECT  32.28 0.016 32.4 0.084 ;
     RECT  32.424 0.016 32.544 0.084 ;
     RECT  32.568 0.016 32.688 0.084 ;
     RECT  32.712 0.016 32.832 0.084 ;
     RECT  32.856 0.016 32.976 0.084 ;
     RECT  33 0.016 33.12 0.084 ;
     RECT  33.144 0.016 33.264 0.084 ;
     RECT  33.288 0.016 33.408 0.084 ;
     RECT  33.432 0.016 33.552 0.084 ;
     RECT  33.576 0.016 33.696 0.084 ;
     RECT  33.72 0.016 33.84 0.084 ;
     RECT  33.864 0.016 33.984 0.084 ;
     RECT  29.52 0.084 34.008 0.085 ;
     RECT  14.568 0.016 14.688 0.084 ;
     RECT  14.712 0.016 14.832 0.084 ;
     RECT  14.856 0.016 14.976 0.084 ;
     RECT  15 0.016 15.12 0.084 ;
     RECT  15.144 0.016 15.264 0.084 ;
     RECT  15.288 0.016 15.408 0.084 ;
     RECT  15.432 0.016 15.552 0.084 ;
     RECT  15.576 0.016 15.696 0.084 ;
     RECT  15.72 0.016 15.84 0.084 ;
     RECT  15.864 0.016 15.984 0.084 ;
     RECT  16.008 0.016 16.128 0.084 ;
     RECT  16.152 0.016 16.272 0.084 ;
     RECT  16.296 0.016 16.416 0.084 ;
     RECT  16.44 0.016 16.56 0.084 ;
     RECT  16.584 0.016 16.704 0.084 ;
     RECT  16.728 0.016 16.848 0.084 ;
     RECT  16.872 0.016 16.992 0.084 ;
     RECT  17.016 0.016 17.136 0.084 ;
     RECT  17.16 0.016 17.28 0.084 ;
     RECT  17.304 0.016 17.424 0.084 ;
     RECT  17.448 0.016 17.568 0.084 ;
     RECT  17.592 0.016 17.712 0.084 ;
     RECT  17.736 0.016 17.856 0.084 ;
     RECT  17.88 0.016 18 0.084 ;
     RECT  18.024 0.016 18.144 0.084 ;
     RECT  18.168 0.016 18.288 0.084 ;
     RECT  18.312 0.016 18.432 0.084 ;
     RECT  18.456 0.016 18.576 0.084 ;
     RECT  18.6 0.016 18.72 0.084 ;
     RECT  18.744 0.016 18.864 0.084 ;
     RECT  18.888 0.016 19.008 0.084 ;
     RECT  19.032 0.016 19.152 0.084 ;
     RECT  19.176 0.016 19.296 0.084 ;
     RECT  19.32 0.016 19.44 0.084 ;
     RECT  19.464 0.016 19.584 0.084 ;
     RECT  19.608 0.016 19.728 0.084 ;
     RECT  19.752 0.016 19.872 0.084 ;
     RECT  19.896 0.016 20.016 0.084 ;
     RECT  20.04 0.016 20.16 0.084 ;
     RECT  20.184 0.016 20.304 0.084 ;
     RECT  20.328 0.016 20.448 0.084 ;
     RECT  20.472 0.016 20.592 0.084 ;
     RECT  20.616 0.016 20.736 0.084 ;
     RECT  20.76 0.016 20.88 0.084 ;
     RECT  20.904 0.016 21.024 0.084 ;
     RECT  21.048 0.016 21.168 0.084 ;
     RECT  21.192 0.016 21.312 0.084 ;
     RECT  21.336 0.016 21.456 0.084 ;
     RECT  21.48 0.016 21.6 0.084 ;
     RECT  21.624 0.016 21.744 0.084 ;
     RECT  21.768 0.016 21.888 0.084 ;
     RECT  21.912 0.016 22.032 0.084 ;
     RECT  22.056 0.016 22.176 0.084 ;
     RECT  22.2 0.016 22.32 0.084 ;
     RECT  22.344 0.016 22.464 0.084 ;
     RECT  22.488 0.016 22.608 0.084 ;
     RECT  22.632 0.016 22.752 0.084 ;
     RECT  22.776 0.016 22.896 0.084 ;
     RECT  22.92 0.016 23.04 0.084 ;
     RECT  23.064 0.016 23.184 0.084 ;
     RECT  23.208 0.016 23.328 0.084 ;
     RECT  23.352 0.016 23.472 0.084 ;
     RECT  23.496 0.016 23.616 0.084 ;
     RECT  23.64 0.016 23.76 0.084 ;
     RECT  23.784 0.016 23.904 0.084 ;
     RECT  23.928 0.016 24.048 0.084 ;
     RECT  24.072 0.016 24.192 0.084 ;
     RECT  24.216 0.016 24.336 0.084 ;
     RECT  24.36 0.016 24.48 0.084 ;
     RECT  24.504 0.016 24.624 0.084 ;
     RECT  24.648 0.016 24.768 0.084 ;
     RECT  24.792 0.016 24.912 0.084 ;
     RECT  24.936 0.016 25.056 0.084 ;
     RECT  25.08 0.016 25.2 0.084 ;
     RECT  25.224 0.016 25.344 0.084 ;
     RECT  25.368 0.016 25.488 0.084 ;
     RECT  25.512 0.016 25.632 0.084 ;
     RECT  25.656 0.016 25.776 0.084 ;
     RECT  25.8 0.016 25.92 0.084 ;
     RECT  25.944 0.016 26.064 0.084 ;
     RECT  26.088 0.016 26.208 0.084 ;
     RECT  26.232 0.016 26.352 0.084 ;
     RECT  26.376 0.016 26.496 0.084 ;
     RECT  26.52 0.016 26.64 0.084 ;
     RECT  26.664 0.016 26.784 0.084 ;
     RECT  26.808 0.016 26.928 0.084 ;
     RECT  26.952 0.016 27.072 0.084 ;
     RECT  27.096 0.016 27.216 0.084 ;
     RECT  27.24 0.016 27.36 0.084 ;
     RECT  27.384 0.016 27.504 0.084 ;
     RECT  27.528 0.016 27.648 0.084 ;
     RECT  27.672 0.016 27.792 0.084 ;
     RECT  27.816 0.016 27.936 0.084 ;
     RECT  27.96 0.016 28.08 0.084 ;
     RECT  28.104 0.016 28.224 0.084 ;
     RECT  14.544 0.084 28.248 1.763 ;
     RECT  14.976 1.763 28.248 1.811 ;
     RECT  29.28 0.085 34.008 2.137 ;
     RECT  2.4 2.137 2.52 2.151 ;
     RECT  5.1 2.137 5.22 2.151 ;
     RECT  7.8 2.137 7.92 2.151 ;
     RECT  10.5 2.137 10.62 2.151 ;
     RECT  13.2 2.137 13.32 2.151 ;
     RECT  29.28 2.137 34.92 2.151 ;
     RECT  37.5 2.137 37.62 2.151 ;
     RECT  40.2 2.137 40.32 2.151 ;
     RECT  14.976 1.811 28.104 2.291 ;
     RECT  29.28 2.151 35.112 2.291 ;
     RECT  29.28 2.291 33.576 2.339 ;
     RECT  15.264 2.291 28.104 2.915 ;
     RECT  29.28 2.339 33.288 3.059 ;
     RECT  15.9 2.915 28.104 3.443 ;
     RECT  29.4 3.059 33.288 3.443 ;
     RECT  15.9 3.443 27.528 4.019 ;
     RECT  31.104 3.443 33.288 4.019 ;
     RECT  31.536 4.019 32.856 4.067 ;
     RECT  15.9 4.019 27.384 4.115 ;
     RECT  31.68 4.067 32.856 4.163 ;
     RECT  31.968 4.163 32.856 4.211 ;
     RECT  17.232 4.115 27.384 4.259 ;
     RECT  32.1 4.211 32.52 4.259 ;
     RECT  17.232 4.259 27.336 4.595 ;
     RECT  17.376 4.595 27.336 4.883 ;
     RECT  17.376 4.883 24.504 4.931 ;
     RECT  15.9 4.115 16.212 5.029 ;
     RECT  18.384 4.931 24.504 5.171 ;
     RECT  15.6 5.029 16.212 5.221 ;
     RECT  25.488 4.883 27.336 5.267 ;
     RECT  32.1 4.259 32.412 5.653 ;
     RECT  26.064 5.267 27.336 5.747 ;
     RECT  24 5.171 24.504 5.843 ;
     RECT  31.92 5.653 32.412 5.845 ;
     RECT  26.112 5.747 27.336 5.987 ;
     RECT  17.376 4.931 17.4 6.323 ;
     RECT  18.384 5.171 18.912 6.323 ;
     RECT  30.72 5.413 30.744 6.323 ;
     RECT  15.36 5.221 16.212 6.805 ;
     RECT  26.208 5.987 27.336 6.805 ;
     RECT  29.4 3.443 29.712 6.805 ;
     RECT  20.208 5.171 22.2 6.899 ;
     RECT  15.024 6.805 16.212 7.237 ;
     RECT  17.328 7.141 17.352 7.237 ;
     RECT  15.024 7.237 17.352 7.381 ;
     RECT  18.6 6.323 18.912 7.381 ;
     RECT  26.208 6.805 27.96 7.475 ;
     RECT  15.024 7.381 18.912 7.619 ;
     RECT  31.92 5.845 32.808 7.669 ;
     RECT  31.92 7.669 32.904 7.811 ;
     RECT  29.136 6.805 29.712 7.859 ;
     RECT  15.9 7.619 18.912 7.907 ;
     RECT  17.328 7.907 18.912 7.909 ;
     RECT  26.208 7.475 27.336 8.003 ;
     RECT  21.12 6.899 22.2 8.195 ;
     RECT  29.4 7.859 29.712 8.197 ;
     RECT  26.208 8.003 27.012 8.243 ;
     RECT  14.784 8.149 14.808 8.291 ;
     RECT  21.3 8.195 22.2 8.579 ;
     RECT  29.4 8.197 30.552 8.723 ;
     RECT  17.328 7.909 19.464 9.011 ;
     RECT  17.664 9.011 19.464 9.203 ;
     RECT  31.968 7.811 32.904 10.547 ;
     RECT  21.3 8.579 21.612 14.725 ;
     RECT  21.12 14.725 21.612 15.875 ;
     RECT  32.1 10.547 32.904 17.077 ;
     RECT  31.968 17.077 32.904 17.461 ;
     RECT  10.5 2.151 10.812 18.181 ;
     RECT  15.9 7.907 16.212 18.229 ;
     RECT  34.8 2.291 35.112 18.373 ;
     RECT  5.1 2.151 5.412 18.421 ;
     RECT  40.2 2.151 40.512 18.421 ;
     RECT  10.224 18.181 10.812 18.565 ;
     RECT  40.08 18.421 40.512 18.709 ;
     RECT  15.264 18.229 16.212 18.757 ;
     RECT  7.8 2.151 8.112 18.805 ;
     RECT  10.224 18.565 10.92 18.805 ;
     RECT  18.6 9.203 19.464 18.805 ;
     RECT  21.3 15.875 21.612 18.805 ;
     RECT  24 5.843 24.312 18.805 ;
     RECT  25.632 18.613 25.656 18.805 ;
     RECT  26.7 8.243 27.012 18.805 ;
     RECT  29.4 8.723 29.712 18.805 ;
     RECT  31.92 17.461 32.904 18.805 ;
     RECT  34.56 18.373 35.112 18.805 ;
     RECT  37.5 2.151 37.812 18.805 ;
     RECT  7.344 18.805 8.808 18.853 ;
     RECT  4.176 18.421 5.412 18.949 ;
     RECT  6.48 18.853 8.808 18.949 ;
     RECT  18.6 18.805 21.612 18.949 ;
     RECT  39.888 18.709 40.512 18.949 ;
     RECT  17.28 18.805 17.304 18.997 ;
     RECT  18.48 18.949 21.612 18.997 ;
     RECT  31.536 18.805 37.812 18.997 ;
     RECT  39.024 18.949 40.512 18.997 ;
     RECT  10.224 18.805 11.4 19.093 ;
     RECT  13.2 2.151 13.512 19.093 ;
     RECT  15.12 18.757 16.212 19.093 ;
     RECT  17.28 18.997 21.612 19.093 ;
     RECT  22.896 18.805 29.712 19.093 ;
     RECT  4.176 18.949 8.808 19.189 ;
     RECT  10.224 19.093 13.512 19.189 ;
     RECT  15.12 19.093 29.712 19.189 ;
     RECT  31.536 18.997 40.512 19.189 ;
     RECT  15.12 19.189 40.512 19.285 ;
     RECT  4.176 19.189 13.512 19.333 ;
     RECT  14.976 19.285 40.512 19.333 ;
     RECT  14.832 19.333 40.92 19.381 ;
     RECT  2.4 2.151 2.712 19.449 ;
     RECT  2.4 19.449 2.52 19.463 ;
     RECT  14.832 19.381 41.064 20.533 ;
     RECT  4.176 19.333 13.656 21.491 ;
     RECT  4.176 21.491 13.56 21.516 ;
     RECT  4.2 21.516 4.32 21.584 ;
     RECT  4.344 21.516 4.464 21.584 ;
     RECT  4.488 21.516 4.608 21.584 ;
     RECT  4.632 21.516 4.752 21.584 ;
     RECT  4.776 21.516 4.896 21.584 ;
     RECT  4.92 21.516 5.04 21.584 ;
     RECT  5.064 21.516 5.184 21.584 ;
     RECT  5.208 21.516 5.328 21.584 ;
     RECT  5.352 21.516 5.472 21.584 ;
     RECT  5.496 21.516 5.616 21.584 ;
     RECT  5.64 21.516 5.76 21.584 ;
     RECT  5.784 21.516 5.904 21.584 ;
     RECT  5.928 21.516 6.048 21.584 ;
     RECT  6.072 21.516 6.192 21.584 ;
     RECT  6.216 21.516 6.336 21.584 ;
     RECT  6.36 21.516 6.48 21.584 ;
     RECT  6.504 21.516 6.624 21.584 ;
     RECT  6.648 21.516 6.768 21.584 ;
     RECT  6.792 21.516 6.912 21.584 ;
     RECT  6.936 21.516 7.056 21.584 ;
     RECT  7.08 21.516 7.2 21.584 ;
     RECT  7.224 21.516 7.344 21.584 ;
     RECT  7.368 21.516 7.488 21.584 ;
     RECT  7.512 21.516 7.632 21.584 ;
     RECT  7.656 21.516 7.776 21.584 ;
     RECT  7.8 21.516 7.92 21.584 ;
     RECT  7.944 21.516 8.064 21.584 ;
     RECT  8.088 21.516 8.208 21.584 ;
     RECT  8.232 21.516 8.352 21.584 ;
     RECT  8.376 21.516 8.496 21.584 ;
     RECT  8.52 21.516 8.64 21.584 ;
     RECT  8.664 21.516 8.784 21.584 ;
     RECT  8.808 21.516 8.928 21.584 ;
     RECT  8.952 21.516 9.072 21.584 ;
     RECT  9.096 21.516 9.216 21.584 ;
     RECT  9.24 21.516 9.36 21.584 ;
     RECT  9.384 21.516 9.504 21.584 ;
     RECT  9.528 21.516 9.648 21.584 ;
     RECT  9.672 21.516 9.792 21.584 ;
     RECT  9.816 21.516 9.936 21.584 ;
     RECT  9.96 21.516 10.08 21.584 ;
     RECT  10.104 21.516 10.224 21.584 ;
     RECT  10.248 21.516 10.368 21.584 ;
     RECT  10.392 21.516 10.512 21.584 ;
     RECT  10.536 21.516 10.656 21.584 ;
     RECT  10.68 21.516 10.8 21.584 ;
     RECT  10.824 21.516 10.944 21.584 ;
     RECT  10.968 21.516 11.088 21.584 ;
     RECT  11.112 21.516 11.232 21.584 ;
     RECT  11.256 21.516 11.376 21.584 ;
     RECT  11.4 21.516 11.52 21.584 ;
     RECT  11.544 21.516 11.664 21.584 ;
     RECT  11.688 21.516 11.808 21.584 ;
     RECT  11.832 21.516 11.952 21.584 ;
     RECT  11.976 21.516 12.096 21.584 ;
     RECT  12.12 21.516 12.24 21.584 ;
     RECT  12.264 21.516 12.384 21.584 ;
     RECT  12.408 21.516 12.528 21.584 ;
     RECT  12.552 21.516 12.672 21.584 ;
     RECT  12.696 21.516 12.816 21.584 ;
     RECT  12.84 21.516 12.96 21.584 ;
     RECT  12.984 21.516 13.104 21.584 ;
     RECT  13.128 21.516 13.248 21.584 ;
     RECT  13.272 21.516 13.392 21.584 ;
     RECT  13.416 21.516 13.536 21.584 ;
     RECT  14.832 20.533 42.36 21.516 ;
     RECT  14.856 21.516 14.976 21.584 ;
     RECT  15 21.516 15.12 21.584 ;
     RECT  15.144 21.516 15.264 21.584 ;
     RECT  15.288 21.516 15.408 21.584 ;
     RECT  15.432 21.516 15.552 21.584 ;
     RECT  15.576 21.516 15.696 21.584 ;
     RECT  15.72 21.516 15.84 21.584 ;
     RECT  15.864 21.516 15.984 21.584 ;
     RECT  16.008 21.516 16.128 21.584 ;
     RECT  16.152 21.516 16.272 21.584 ;
     RECT  16.296 21.516 16.416 21.584 ;
     RECT  16.44 21.516 16.56 21.584 ;
     RECT  16.584 21.516 16.704 21.584 ;
     RECT  16.728 21.516 16.848 21.584 ;
     RECT  16.872 21.516 16.992 21.584 ;
     RECT  17.016 21.516 17.136 21.584 ;
     RECT  17.16 21.516 17.28 21.584 ;
     RECT  17.304 21.516 17.424 21.584 ;
     RECT  17.448 21.516 17.568 21.584 ;
     RECT  17.592 21.516 17.712 21.584 ;
     RECT  17.736 21.516 17.856 21.584 ;
     RECT  17.88 21.516 18 21.584 ;
     RECT  18.024 21.516 18.144 21.584 ;
     RECT  18.168 21.516 18.288 21.584 ;
     RECT  18.312 21.516 18.432 21.584 ;
     RECT  18.456 21.516 18.576 21.584 ;
     RECT  18.6 21.516 18.72 21.584 ;
     RECT  18.744 21.516 18.864 21.584 ;
     RECT  18.888 21.516 19.008 21.584 ;
     RECT  19.032 21.516 19.152 21.584 ;
     RECT  19.176 21.516 19.296 21.584 ;
     RECT  19.32 21.516 19.44 21.584 ;
     RECT  19.464 21.516 19.584 21.584 ;
     RECT  19.608 21.516 19.728 21.584 ;
     RECT  19.752 21.516 19.872 21.584 ;
     RECT  19.896 21.516 20.016 21.584 ;
     RECT  20.04 21.516 20.16 21.584 ;
     RECT  20.184 21.516 20.304 21.584 ;
     RECT  20.328 21.516 20.448 21.584 ;
     RECT  20.472 21.516 20.592 21.584 ;
     RECT  20.616 21.516 20.736 21.584 ;
     RECT  20.76 21.516 20.88 21.584 ;
     RECT  20.904 21.516 21.024 21.584 ;
     RECT  21.048 21.516 21.168 21.584 ;
     RECT  21.192 21.516 21.312 21.584 ;
     RECT  21.336 21.516 21.456 21.584 ;
     RECT  21.48 21.516 21.6 21.584 ;
     RECT  21.624 21.516 21.744 21.584 ;
     RECT  21.768 21.516 21.888 21.584 ;
     RECT  21.912 21.516 22.032 21.584 ;
     RECT  22.056 21.516 22.176 21.584 ;
     RECT  22.2 21.516 22.32 21.584 ;
     RECT  22.344 21.516 22.464 21.584 ;
     RECT  22.488 21.516 22.608 21.584 ;
     RECT  22.632 21.516 22.752 21.584 ;
     RECT  22.776 21.516 22.896 21.584 ;
     RECT  22.92 21.516 23.04 21.584 ;
     RECT  23.064 21.516 23.184 21.584 ;
     RECT  23.208 21.516 23.328 21.584 ;
     RECT  23.352 21.516 23.472 21.584 ;
     RECT  23.496 21.516 23.616 21.584 ;
     RECT  23.64 21.516 23.76 21.584 ;
     RECT  23.784 21.516 23.904 21.584 ;
     RECT  23.928 21.516 24.048 21.584 ;
     RECT  24.072 21.516 24.192 21.584 ;
     RECT  24.216 21.516 24.336 21.584 ;
     RECT  24.36 21.516 24.48 21.584 ;
     RECT  24.504 21.516 24.624 21.584 ;
     RECT  24.648 21.516 24.768 21.584 ;
     RECT  24.792 21.516 24.912 21.584 ;
     RECT  24.936 21.516 25.056 21.584 ;
     RECT  25.08 21.516 25.2 21.584 ;
     RECT  25.224 21.516 25.344 21.584 ;
     RECT  25.368 21.516 25.488 21.584 ;
     RECT  25.512 21.516 25.632 21.584 ;
     RECT  25.656 21.516 25.776 21.584 ;
     RECT  25.8 21.516 25.92 21.584 ;
     RECT  25.944 21.516 26.064 21.584 ;
     RECT  26.088 21.516 26.208 21.584 ;
     RECT  26.232 21.516 26.352 21.584 ;
     RECT  26.376 21.516 26.496 21.584 ;
     RECT  26.52 21.516 26.64 21.584 ;
     RECT  26.664 21.516 26.784 21.584 ;
     RECT  26.808 21.516 26.928 21.584 ;
     RECT  26.952 21.516 27.072 21.584 ;
     RECT  27.096 21.516 27.216 21.584 ;
     RECT  27.24 21.516 27.36 21.584 ;
     RECT  27.384 21.516 27.504 21.584 ;
     RECT  27.528 21.516 27.648 21.584 ;
     RECT  27.672 21.516 27.792 21.584 ;
     RECT  27.816 21.516 27.936 21.584 ;
     RECT  27.96 21.516 28.08 21.584 ;
     RECT  28.104 21.516 28.224 21.584 ;
     RECT  28.248 21.516 28.368 21.584 ;
     RECT  28.392 21.516 28.512 21.584 ;
     RECT  28.536 21.516 28.656 21.584 ;
     RECT  28.68 21.516 28.8 21.584 ;
     RECT  28.824 21.516 28.944 21.584 ;
     RECT  28.968 21.516 29.088 21.584 ;
     RECT  29.112 21.516 29.232 21.584 ;
     RECT  29.256 21.516 29.376 21.584 ;
     RECT  29.4 21.516 29.52 21.584 ;
     RECT  29.544 21.516 29.664 21.584 ;
     RECT  29.688 21.516 29.808 21.584 ;
     RECT  29.832 21.516 29.952 21.584 ;
     RECT  29.976 21.516 30.096 21.584 ;
     RECT  30.12 21.516 30.24 21.584 ;
     RECT  30.264 21.516 30.384 21.584 ;
     RECT  30.408 21.516 30.528 21.584 ;
     RECT  30.552 21.516 30.672 21.584 ;
     RECT  30.696 21.516 30.816 21.584 ;
     RECT  30.84 21.516 30.96 21.584 ;
     RECT  30.984 21.516 31.104 21.584 ;
     RECT  31.128 21.516 31.248 21.584 ;
     RECT  31.272 21.516 31.392 21.584 ;
     RECT  31.416 21.516 31.536 21.584 ;
     RECT  31.56 21.516 31.68 21.584 ;
     RECT  31.704 21.516 31.824 21.584 ;
     RECT  31.848 21.516 31.968 21.584 ;
     RECT  31.992 21.516 32.112 21.584 ;
     RECT  32.136 21.516 32.256 21.584 ;
     RECT  32.28 21.516 32.4 21.584 ;
     RECT  32.424 21.516 32.544 21.584 ;
     RECT  32.568 21.516 32.688 21.584 ;
     RECT  32.712 21.516 32.832 21.584 ;
     RECT  32.856 21.516 32.976 21.584 ;
     RECT  33 21.516 33.12 21.584 ;
     RECT  33.144 21.516 33.264 21.584 ;
     RECT  33.288 21.516 33.408 21.584 ;
     RECT  33.432 21.516 33.552 21.584 ;
     RECT  33.576 21.516 33.696 21.584 ;
     RECT  33.72 21.516 33.84 21.584 ;
     RECT  33.864 21.516 33.984 21.584 ;
     RECT  34.008 21.516 34.128 21.584 ;
     RECT  34.152 21.516 34.272 21.584 ;
     RECT  34.296 21.516 34.416 21.584 ;
     RECT  34.44 21.516 34.56 21.584 ;
     RECT  34.584 21.516 34.704 21.584 ;
     RECT  34.728 21.516 34.848 21.584 ;
     RECT  34.872 21.516 34.992 21.584 ;
     RECT  35.016 21.516 35.136 21.584 ;
     RECT  35.16 21.516 35.28 21.584 ;
     RECT  35.304 21.516 35.424 21.584 ;
     RECT  35.448 21.516 35.568 21.584 ;
     RECT  35.592 21.516 35.712 21.584 ;
     RECT  35.736 21.516 35.856 21.584 ;
     RECT  35.88 21.516 36 21.584 ;
     RECT  36.024 21.516 36.144 21.584 ;
     RECT  36.168 21.516 36.288 21.584 ;
     RECT  36.312 21.516 36.432 21.584 ;
     RECT  36.456 21.516 36.576 21.584 ;
     RECT  36.6 21.516 36.72 21.584 ;
     RECT  36.744 21.516 36.864 21.584 ;
     RECT  36.888 21.516 37.008 21.584 ;
     RECT  37.032 21.516 37.152 21.584 ;
     RECT  37.176 21.516 37.296 21.584 ;
     RECT  37.32 21.516 37.44 21.584 ;
     RECT  37.464 21.516 37.584 21.584 ;
     RECT  37.608 21.516 37.728 21.584 ;
     RECT  37.752 21.516 37.872 21.584 ;
     RECT  37.896 21.516 38.016 21.584 ;
     RECT  38.04 21.516 38.16 21.584 ;
     RECT  38.184 21.516 38.304 21.584 ;
     RECT  38.328 21.516 38.448 21.584 ;
     RECT  38.472 21.516 38.592 21.584 ;
     RECT  38.616 21.516 38.736 21.584 ;
     RECT  38.76 21.516 38.88 21.584 ;
     RECT  38.904 21.516 39.024 21.584 ;
     RECT  39.048 21.516 39.168 21.584 ;
     RECT  39.192 21.516 39.312 21.584 ;
     RECT  39.336 21.516 39.456 21.584 ;
     RECT  39.48 21.516 39.6 21.584 ;
     RECT  39.624 21.516 39.744 21.584 ;
     RECT  39.768 21.516 39.888 21.584 ;
     RECT  39.912 21.516 40.032 21.584 ;
     RECT  40.056 21.516 40.176 21.584 ;
     RECT  40.2 21.516 40.32 21.584 ;
     RECT  40.344 21.516 40.464 21.584 ;
     RECT  40.488 21.516 40.608 21.584 ;
     RECT  40.632 21.516 40.752 21.584 ;
     RECT  40.776 21.516 40.896 21.584 ;
     RECT  40.92 21.516 41.04 21.584 ;
     RECT  41.064 21.516 41.184 21.584 ;
     RECT  41.208 21.516 41.328 21.584 ;
     RECT  41.352 21.516 41.472 21.584 ;
     RECT  41.496 21.516 41.616 21.584 ;
     RECT  41.64 21.516 41.76 21.584 ;
     RECT  41.784 21.516 41.904 21.584 ;
     RECT  41.928 21.516 42.048 21.584 ;
     RECT  42.072 21.516 42.192 21.584 ;
     RECT  42.216 21.516 42.336 21.584 ;
     RECT  28.296 0.016 29.472 0.085 ;
     RECT  28.296 0.085 29.28 0.132 ;
     RECT  28.248 0.132 29.28 1.811 ;
     RECT  14.544 1.763 14.976 2.137 ;
     RECT  28.104 1.811 29.28 3.059 ;
     RECT  13.32 2.137 14.976 2.151 ;
     RECT  13.512 2.151 14.976 2.291 ;
     RECT  33.576 2.291 34.8 2.339 ;
     RECT  33.288 2.339 34.8 4.019 ;
     RECT  28.104 3.059 29.4 3.443 ;
     RECT  29.712 3.443 31.104 4.019 ;
     RECT  29.712 4.019 31.536 4.067 ;
     RECT  29.712 4.067 31.68 4.163 ;
     RECT  16.212 4.115 17.232 4.595 ;
     RECT  29.712 4.163 31.968 4.211 ;
     RECT  29.712 4.211 32.1 5.413 ;
     RECT  16.212 4.595 17.376 6.323 ;
     RECT  24.504 4.883 25.488 5.267 ;
     RECT  17.4 4.931 18.384 6.323 ;
     RECT  18.912 5.171 20.208 6.899 ;
     RECT  29.712 5.413 30.72 6.323 ;
     RECT  30.744 5.413 32.1 5.653 ;
     RECT  30.744 5.653 31.92 6.323 ;
     RECT  16.212 6.323 18.6 7.141 ;
     RECT  13.512 6.805 15.024 7.619 ;
     RECT  27.96 6.805 29.136 7.475 ;
     RECT  18.912 6.899 19.464 7.909 ;
     RECT  16.212 7.141 17.328 7.237 ;
     RECT  17.352 7.141 18.6 7.381 ;
     RECT  13.512 7.619 15.9 8.149 ;
     RECT  31.92 7.811 31.968 8.197 ;
     RECT  16.212 7.907 17.328 9.011 ;
     RECT  13.512 8.149 14.784 8.291 ;
     RECT  14.808 8.149 15.9 8.291 ;
     RECT  30.552 8.197 31.968 8.723 ;
     RECT  16.212 9.011 17.664 9.203 ;
     RECT  2.712 18.421 4.176 19.449 ;
     RECT  24.312 18.613 25.632 18.805 ;
     RECT  25.656 18.613 26.7 18.805 ;
     RECT  8.808 18.805 10.224 19.189 ;
     RECT  16.212 18.805 17.28 19.093 ;
     RECT  17.304 18.805 18.6 18.949 ;
     RECT  21.612 18.805 22.896 19.093 ;
     RECT  5.412 18.853 6.48 18.949 ;
     RECT  17.304 18.949 18.48 18.997 ;
     RECT  37.812 18.949 39.024 18.997 ;
     RECT  13.512 19.285 14.976 19.333 ;
     RECT  13.656 19.333 14.832 21.468 ;
     RECT  13.656 21.468 14.784 21.491 ;
     RECT  13.608 21.491 14.784 21.584 ;
  END
END qkd_seq_xd_sel
END LIBRARY
